VERSION 5.8 ;
BUSBITCHARS "[]" ;
DIVIDERCHAR "/" ;
UNITS
    DATABASE MICRONS 1000 ;
END UNITS

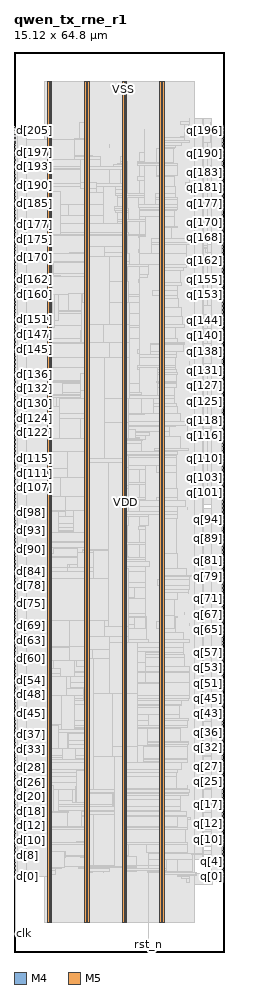
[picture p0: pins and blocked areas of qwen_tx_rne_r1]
MACRO qwen_tx_rne_r1
  FOREIGN qwen_tx_rne_r1 0 0 ;
  CLASS BLOCK ;
  SIZE 15.12 BY 64.8 ;
  PIN clk
    DIRECTION INPUT ;
    USE SIGNAL ;
    PORT
      LAYER M4 ;
        RECT  0.054 1.296 0.138 1.32 ;
    END
    PORT
      LAYER M4 ;
        RECT  0.108 1.296 0.227 1.416 ;
    END
  END clk
  PIN d[0]
    DIRECTION INPUT ;
    USE SIGNAL ;
    PORT
      LAYER M4 ;
        RECT  0.054 5.424 0.138 5.448 ;
    END
  END d[0]
  PIN d[100]
    DIRECTION INPUT ;
    USE SIGNAL ;
    PORT
      LAYER M4 ;
        RECT  0.054 31.584 0.138 31.608 ;
    END
  END d[100]
  PIN d[101]
    DIRECTION INPUT ;
    USE SIGNAL ;
    PORT
      LAYER M4 ;
        RECT  0.054 31.872 0.138 31.896 ;
    END
  END d[101]
  PIN d[102]
    DIRECTION INPUT ;
    USE SIGNAL ;
    PORT
      LAYER M4 ;
        RECT  0.054 32.112 0.138 32.136 ;
    END
  END d[102]
  PIN d[103]
    DIRECTION INPUT ;
    USE SIGNAL ;
    PORT
      LAYER M4 ;
        RECT  0.054 32.4 0.138 32.424 ;
    END
  END d[103]
  PIN d[104]
    DIRECTION INPUT ;
    USE SIGNAL ;
    PORT
      LAYER M4 ;
        RECT  0.054 32.64 0.138 32.664 ;
    END
  END d[104]
  PIN d[105]
    DIRECTION INPUT ;
    USE SIGNAL ;
    PORT
      LAYER M4 ;
        RECT  0.054 32.928 0.138 32.952 ;
    END
  END d[105]
  PIN d[106]
    DIRECTION INPUT ;
    USE SIGNAL ;
    PORT
      LAYER M4 ;
        RECT  0.054 33.168 0.138 33.192 ;
    END
  END d[106]
  PIN d[107]
    DIRECTION INPUT ;
    USE SIGNAL ;
    PORT
      LAYER M4 ;
        RECT  0.054 33.456 0.138 33.48 ;
    END
  END d[107]
  PIN d[108]
    DIRECTION INPUT ;
    USE SIGNAL ;
    PORT
      LAYER M4 ;
        RECT  0.054 33.696 0.138 33.72 ;
    END
  END d[108]
  PIN d[109]
    DIRECTION INPUT ;
    USE SIGNAL ;
    PORT
      LAYER M4 ;
        RECT  0.054 33.984 0.138 34.008 ;
    END
  END d[109]
  PIN d[10]
    DIRECTION INPUT ;
    USE SIGNAL ;
    PORT
      LAYER M4 ;
        RECT  0.054 8.016 0.138 8.04 ;
    END
  END d[10]
  PIN d[110]
    DIRECTION INPUT ;
    USE SIGNAL ;
    PORT
      LAYER M4 ;
        RECT  0.054 34.224 0.138 34.248 ;
    END
  END d[110]
  PIN d[111]
    DIRECTION INPUT ;
    USE SIGNAL ;
    PORT
      LAYER M4 ;
        RECT  0.054 34.464 0.138 34.488 ;
    END
  END d[111]
  PIN d[112]
    DIRECTION INPUT ;
    USE SIGNAL ;
    PORT
      LAYER M4 ;
        RECT  0.054 34.752 0.138 34.776 ;
    END
  END d[112]
  PIN d[113]
    DIRECTION INPUT ;
    USE SIGNAL ;
    PORT
      LAYER M4 ;
        RECT  0.054 34.992 0.138 35.016 ;
    END
  END d[113]
  PIN d[114]
    DIRECTION INPUT ;
    USE SIGNAL ;
    PORT
      LAYER M4 ;
        RECT  0.054 35.28 0.138 35.304 ;
    END
  END d[114]
  PIN d[115]
    DIRECTION INPUT ;
    USE SIGNAL ;
    PORT
      LAYER M4 ;
        RECT  0.054 35.52 0.138 35.544 ;
    END
  END d[115]
  PIN d[116]
    DIRECTION INPUT ;
    USE SIGNAL ;
    PORT
      LAYER M4 ;
        RECT  0.054 35.808 0.138 35.832 ;
    END
  END d[116]
  PIN d[117]
    DIRECTION INPUT ;
    USE SIGNAL ;
    PORT
      LAYER M4 ;
        RECT  0.054 36.048 0.138 36.072 ;
    END
  END d[117]
  PIN d[118]
    DIRECTION INPUT ;
    USE SIGNAL ;
    PORT
      LAYER M4 ;
        RECT  0.054 36.336 0.138 36.36 ;
    END
  END d[118]
  PIN d[119]
    DIRECTION INPUT ;
    USE SIGNAL ;
    PORT
      LAYER M4 ;
        RECT  0.054 36.576 0.138 36.6 ;
    END
  END d[119]
  PIN d[11]
    DIRECTION INPUT ;
    USE SIGNAL ;
    PORT
      LAYER M4 ;
        RECT  0.054 8.256 0.138 8.28 ;
    END
  END d[11]
  PIN d[120]
    DIRECTION INPUT ;
    USE SIGNAL ;
    PORT
      LAYER M4 ;
        RECT  0.054 36.864 0.138 36.888 ;
    END
  END d[120]
  PIN d[121]
    DIRECTION INPUT ;
    USE SIGNAL ;
    PORT
      LAYER M4 ;
        RECT  0.054 37.104 0.138 37.128 ;
    END
  END d[121]
  PIN d[122]
    DIRECTION INPUT ;
    USE SIGNAL ;
    PORT
      LAYER M4 ;
        RECT  0.054 37.392 0.138 37.416 ;
    END
  END d[122]
  PIN d[123]
    DIRECTION INPUT ;
    USE SIGNAL ;
    PORT
      LAYER M4 ;
        RECT  0.054 37.632 0.138 37.656 ;
    END
  END d[123]
  PIN d[124]
    DIRECTION INPUT ;
    USE SIGNAL ;
    PORT
      LAYER M4 ;
        RECT  0.054 37.872 0.138 37.896 ;
    END
  END d[124]
  PIN d[125]
    DIRECTION INPUT ;
    USE SIGNAL ;
    PORT
      LAYER M4 ;
        RECT  0.054 38.16 0.138 38.184 ;
    END
  END d[125]
  PIN d[126]
    DIRECTION INPUT ;
    USE SIGNAL ;
    PORT
      LAYER M4 ;
        RECT  0.054 38.4 0.138 38.424 ;
    END
  END d[126]
  PIN d[127]
    DIRECTION INPUT ;
    USE SIGNAL ;
    PORT
      LAYER M4 ;
        RECT  0.054 38.688 0.138 38.712 ;
    END
  END d[127]
  PIN d[128]
    DIRECTION INPUT ;
    USE SIGNAL ;
    PORT
      LAYER M4 ;
        RECT  0.054 38.928 0.138 38.952 ;
    END
  END d[128]
  PIN d[129]
    DIRECTION INPUT ;
    USE SIGNAL ;
    PORT
      LAYER M4 ;
        RECT  0.054 39.216 0.138 39.24 ;
    END
  END d[129]
  PIN d[12]
    DIRECTION INPUT ;
    USE SIGNAL ;
    PORT
      LAYER M4 ;
        RECT  0.054 8.544 0.138 8.568 ;
    END
  END d[12]
  PIN d[130]
    DIRECTION INPUT ;
    USE SIGNAL ;
    PORT
      LAYER M4 ;
        RECT  0.054 39.456 0.138 39.48 ;
    END
  END d[130]
  PIN d[131]
    DIRECTION INPUT ;
    USE SIGNAL ;
    PORT
      LAYER M4 ;
        RECT  0.054 39.744 0.138 39.768 ;
    END
  END d[131]
  PIN d[132]
    DIRECTION INPUT ;
    USE SIGNAL ;
    PORT
      LAYER M4 ;
        RECT  0.054 39.984 0.138 40.008 ;
    END
  END d[132]
  PIN d[133]
    DIRECTION INPUT ;
    USE SIGNAL ;
    PORT
      LAYER M4 ;
        RECT  0.054 40.272 0.138 40.296 ;
    END
  END d[133]
  PIN d[134]
    DIRECTION INPUT ;
    USE SIGNAL ;
    PORT
      LAYER M4 ;
        RECT  0.054 40.512 0.138 40.536 ;
    END
  END d[134]
  PIN d[135]
    DIRECTION INPUT ;
    USE SIGNAL ;
    PORT
      LAYER M4 ;
        RECT  0.054 40.8 0.138 40.824 ;
    END
  END d[135]
  PIN d[136]
    DIRECTION INPUT ;
    USE SIGNAL ;
    PORT
      LAYER M4 ;
        RECT  0.054 41.04 0.138 41.064 ;
    END
  END d[136]
  PIN d[137]
    DIRECTION INPUT ;
    USE SIGNAL ;
    PORT
      LAYER M4 ;
        RECT  0.054 41.28 0.138 41.304 ;
    END
  END d[137]
  PIN d[138]
    DIRECTION INPUT ;
    USE SIGNAL ;
    PORT
      LAYER M4 ;
        RECT  0.054 41.568 0.138 41.592 ;
    END
  END d[138]
  PIN d[139]
    DIRECTION INPUT ;
    USE SIGNAL ;
    PORT
      LAYER M4 ;
        RECT  0.054 41.808 0.138 41.832 ;
    END
  END d[139]
  PIN d[13]
    DIRECTION INPUT ;
    USE SIGNAL ;
    PORT
      LAYER M4 ;
        RECT  0.054 8.784 0.138 8.808 ;
    END
  END d[13]
  PIN d[140]
    DIRECTION INPUT ;
    USE SIGNAL ;
    PORT
      LAYER M4 ;
        RECT  0.054 42.096 0.138 42.12 ;
    END
  END d[140]
  PIN d[141]
    DIRECTION INPUT ;
    USE SIGNAL ;
    PORT
      LAYER M4 ;
        RECT  0.054 42.336 0.138 42.36 ;
    END
  END d[141]
  PIN d[142]
    DIRECTION INPUT ;
    USE SIGNAL ;
    PORT
      LAYER M4 ;
        RECT  0.054 42.624 0.138 42.648 ;
    END
  END d[142]
  PIN d[143]
    DIRECTION INPUT ;
    USE SIGNAL ;
    PORT
      LAYER M4 ;
        RECT  0.054 42.864 0.138 42.888 ;
    END
  END d[143]
  PIN d[144]
    DIRECTION INPUT ;
    USE SIGNAL ;
    PORT
      LAYER M4 ;
        RECT  0.054 43.152 0.138 43.176 ;
    END
  END d[144]
  PIN d[145]
    DIRECTION INPUT ;
    USE SIGNAL ;
    PORT
      LAYER M4 ;
        RECT  0.054 43.392 0.138 43.416 ;
    END
  END d[145]
  PIN d[146]
    DIRECTION INPUT ;
    USE SIGNAL ;
    PORT
      LAYER M4 ;
        RECT  0.054 43.68 0.138 43.704 ;
    END
  END d[146]
  PIN d[147]
    DIRECTION INPUT ;
    USE SIGNAL ;
    PORT
      LAYER M4 ;
        RECT  0.054 43.92 0.138 43.944 ;
    END
  END d[147]
  PIN d[148]
    DIRECTION INPUT ;
    USE SIGNAL ;
    PORT
      LAYER M4 ;
        RECT  0.054 44.208 0.138 44.232 ;
    END
  END d[148]
  PIN d[149]
    DIRECTION INPUT ;
    USE SIGNAL ;
    PORT
      LAYER M4 ;
        RECT  0.054 44.448 0.138 44.472 ;
    END
  END d[149]
  PIN d[14]
    DIRECTION INPUT ;
    USE SIGNAL ;
    PORT
      LAYER M4 ;
        RECT  0.054 9.072 0.138 9.096 ;
    END
  END d[14]
  PIN d[150]
    DIRECTION INPUT ;
    USE SIGNAL ;
    PORT
      LAYER M4 ;
        RECT  0.054 44.688 0.138 44.712 ;
    END
  END d[150]
  PIN d[151]
    DIRECTION INPUT ;
    USE SIGNAL ;
    PORT
      LAYER M4 ;
        RECT  0.054 44.976 0.138 45 ;
    END
  END d[151]
  PIN d[152]
    DIRECTION INPUT ;
    USE SIGNAL ;
    PORT
      LAYER M4 ;
        RECT  0.054 45.216 0.138 45.24 ;
    END
  END d[152]
  PIN d[153]
    DIRECTION INPUT ;
    USE SIGNAL ;
    PORT
      LAYER M4 ;
        RECT  0.054 45.504 0.138 45.528 ;
    END
  END d[153]
  PIN d[154]
    DIRECTION INPUT ;
    USE SIGNAL ;
    PORT
      LAYER M4 ;
        RECT  0.054 45.744 0.138 45.768 ;
    END
  END d[154]
  PIN d[155]
    DIRECTION INPUT ;
    USE SIGNAL ;
    PORT
      LAYER M4 ;
        RECT  0.054 46.032 0.138 46.056 ;
    END
  END d[155]
  PIN d[156]
    DIRECTION INPUT ;
    USE SIGNAL ;
    PORT
      LAYER M4 ;
        RECT  0.054 46.272 0.138 46.296 ;
    END
  END d[156]
  PIN d[157]
    DIRECTION INPUT ;
    USE SIGNAL ;
    PORT
      LAYER M4 ;
        RECT  0.054 46.56 0.138 46.584 ;
    END
  END d[157]
  PIN d[158]
    DIRECTION INPUT ;
    USE SIGNAL ;
    PORT
      LAYER M4 ;
        RECT  0.054 46.8 0.138 46.824 ;
    END
  END d[158]
  PIN d[159]
    DIRECTION INPUT ;
    USE SIGNAL ;
    PORT
      LAYER M4 ;
        RECT  0.054 47.088 0.138 47.112 ;
    END
  END d[159]
  PIN d[15]
    DIRECTION INPUT ;
    USE SIGNAL ;
    PORT
      LAYER M4 ;
        RECT  0.054 9.312 0.138 9.336 ;
    END
  END d[15]
  PIN d[160]
    DIRECTION INPUT ;
    USE SIGNAL ;
    PORT
      LAYER M4 ;
        RECT  0.054 47.328 0.138 47.352 ;
    END
  END d[160]
  PIN d[161]
    DIRECTION INPUT ;
    USE SIGNAL ;
    PORT
      LAYER M4 ;
        RECT  0.054 47.568 0.138 47.592 ;
    END
  END d[161]
  PIN d[162]
    DIRECTION INPUT ;
    USE SIGNAL ;
    PORT
      LAYER M4 ;
        RECT  0.054 47.856 0.138 47.88 ;
    END
  END d[162]
  PIN d[163]
    DIRECTION INPUT ;
    USE SIGNAL ;
    PORT
      LAYER M4 ;
        RECT  0.054 48.096 0.138 48.12 ;
    END
  END d[163]
  PIN d[164]
    DIRECTION INPUT ;
    USE SIGNAL ;
    PORT
      LAYER M4 ;
        RECT  0.054 48.384 0.138 48.408 ;
    END
  END d[164]
  PIN d[165]
    DIRECTION INPUT ;
    USE SIGNAL ;
    PORT
      LAYER M4 ;
        RECT  0.054 48.624 0.138 48.648 ;
    END
  END d[165]
  PIN d[166]
    DIRECTION INPUT ;
    USE SIGNAL ;
    PORT
      LAYER M4 ;
        RECT  0.054 48.912 0.138 48.936 ;
    END
  END d[166]
  PIN d[167]
    DIRECTION INPUT ;
    USE SIGNAL ;
    PORT
      LAYER M4 ;
        RECT  0.054 49.152 0.138 49.176 ;
    END
  END d[167]
  PIN d[168]
    DIRECTION INPUT ;
    USE SIGNAL ;
    PORT
      LAYER M4 ;
        RECT  0.054 49.44 0.138 49.464 ;
    END
  END d[168]
  PIN d[169]
    DIRECTION INPUT ;
    USE SIGNAL ;
    PORT
      LAYER M4 ;
        RECT  0.054 49.68 0.138 49.704 ;
    END
  END d[169]
  PIN d[16]
    DIRECTION INPUT ;
    USE SIGNAL ;
    PORT
      LAYER M4 ;
        RECT  0.054 9.6 0.138 9.624 ;
    END
  END d[16]
  PIN d[170]
    DIRECTION INPUT ;
    USE SIGNAL ;
    PORT
      LAYER M4 ;
        RECT  0.054 49.968 0.138 49.992 ;
    END
  END d[170]
  PIN d[171]
    DIRECTION INPUT ;
    USE SIGNAL ;
    PORT
      LAYER M4 ;
        RECT  0.054 50.208 0.138 50.232 ;
    END
  END d[171]
  PIN d[172]
    DIRECTION INPUT ;
    USE SIGNAL ;
    PORT
      LAYER M4 ;
        RECT  0.054 50.496 0.138 50.52 ;
    END
  END d[172]
  PIN d[173]
    DIRECTION INPUT ;
    USE SIGNAL ;
    PORT
      LAYER M4 ;
        RECT  0.054 50.736 0.138 50.76 ;
    END
  END d[173]
  PIN d[174]
    DIRECTION INPUT ;
    USE SIGNAL ;
    PORT
      LAYER M4 ;
        RECT  0.054 50.976 0.138 51 ;
    END
  END d[174]
  PIN d[175]
    DIRECTION INPUT ;
    USE SIGNAL ;
    PORT
      LAYER M4 ;
        RECT  0.054 51.264 0.138 51.288 ;
    END
  END d[175]
  PIN d[176]
    DIRECTION INPUT ;
    USE SIGNAL ;
    PORT
      LAYER M4 ;
        RECT  0.054 51.504 0.138 51.528 ;
    END
  END d[176]
  PIN d[177]
    DIRECTION INPUT ;
    USE SIGNAL ;
    PORT
      LAYER M4 ;
        RECT  0.054 51.792 0.138 51.816 ;
    END
  END d[177]
  PIN d[178]
    DIRECTION INPUT ;
    USE SIGNAL ;
    PORT
      LAYER M4 ;
        RECT  0.054 52.032 0.138 52.056 ;
    END
  END d[178]
  PIN d[179]
    DIRECTION INPUT ;
    USE SIGNAL ;
    PORT
      LAYER M4 ;
        RECT  0.054 52.32 0.138 52.344 ;
    END
  END d[179]
  PIN d[17]
    DIRECTION INPUT ;
    USE SIGNAL ;
    PORT
      LAYER M4 ;
        RECT  0.054 9.84 0.138 9.864 ;
    END
  END d[17]
  PIN d[180]
    DIRECTION INPUT ;
    USE SIGNAL ;
    PORT
      LAYER M4 ;
        RECT  0.054 52.56 0.138 52.584 ;
    END
  END d[180]
  PIN d[181]
    DIRECTION INPUT ;
    USE SIGNAL ;
    PORT
      LAYER M4 ;
        RECT  0.054 52.848 0.138 52.872 ;
    END
  END d[181]
  PIN d[182]
    DIRECTION INPUT ;
    USE SIGNAL ;
    PORT
      LAYER M4 ;
        RECT  0.054 53.088 0.138 53.112 ;
    END
  END d[182]
  PIN d[183]
    DIRECTION INPUT ;
    USE SIGNAL ;
    PORT
      LAYER M4 ;
        RECT  0.054 53.376 0.138 53.4 ;
    END
  END d[183]
  PIN d[184]
    DIRECTION INPUT ;
    USE SIGNAL ;
    PORT
      LAYER M4 ;
        RECT  0.054 53.616 0.138 53.64 ;
    END
  END d[184]
  PIN d[185]
    DIRECTION INPUT ;
    USE SIGNAL ;
    PORT
      LAYER M4 ;
        RECT  0.054 53.904 0.138 53.928 ;
    END
  END d[185]
  PIN d[186]
    DIRECTION INPUT ;
    USE SIGNAL ;
    PORT
      LAYER M4 ;
        RECT  0.054 54.144 0.138 54.168 ;
    END
  END d[186]
  PIN d[187]
    DIRECTION INPUT ;
    USE SIGNAL ;
    PORT
      LAYER M4 ;
        RECT  0.054 54.384 0.138 54.408 ;
    END
  END d[187]
  PIN d[188]
    DIRECTION INPUT ;
    USE SIGNAL ;
    PORT
      LAYER M4 ;
        RECT  0.054 54.672 0.138 54.696 ;
    END
  END d[188]
  PIN d[189]
    DIRECTION INPUT ;
    USE SIGNAL ;
    PORT
      LAYER M4 ;
        RECT  0.054 54.912 0.138 54.936 ;
    END
  END d[189]
  PIN d[18]
    DIRECTION INPUT ;
    USE SIGNAL ;
    PORT
      LAYER M4 ;
        RECT  0.054 10.128 0.138 10.152 ;
    END
  END d[18]
  PIN d[190]
    DIRECTION INPUT ;
    USE SIGNAL ;
    PORT
      LAYER M4 ;
        RECT  0.054 55.2 0.138 55.224 ;
    END
  END d[190]
  PIN d[191]
    DIRECTION INPUT ;
    USE SIGNAL ;
    PORT
      LAYER M4 ;
        RECT  0.054 55.44 0.138 55.464 ;
    END
  END d[191]
  PIN d[192]
    DIRECTION INPUT ;
    USE SIGNAL ;
    PORT
      LAYER M4 ;
        RECT  0.054 55.728 0.138 55.752 ;
    END
  END d[192]
  PIN d[193]
    DIRECTION INPUT ;
    USE SIGNAL ;
    PORT
      LAYER M4 ;
        RECT  0.054 55.968 0.138 55.992 ;
    END
  END d[193]
  PIN d[194]
    DIRECTION INPUT ;
    USE SIGNAL ;
    PORT
      LAYER M4 ;
        RECT  0.054 56.256 0.138 56.28 ;
    END
  END d[194]
  PIN d[195]
    DIRECTION INPUT ;
    USE SIGNAL ;
    PORT
      LAYER M4 ;
        RECT  0.054 56.496 0.138 56.52 ;
    END
  END d[195]
  PIN d[196]
    DIRECTION INPUT ;
    USE SIGNAL ;
    PORT
      LAYER M4 ;
        RECT  0.054 56.784 0.138 56.808 ;
    END
  END d[196]
  PIN d[197]
    DIRECTION INPUT ;
    USE SIGNAL ;
    PORT
      LAYER M4 ;
        RECT  0.054 57.024 0.138 57.048 ;
    END
  END d[197]
  PIN d[198]
    DIRECTION INPUT ;
    USE SIGNAL ;
    PORT
      LAYER M4 ;
        RECT  0.054 57.312 0.138 57.336 ;
    END
  END d[198]
  PIN d[199]
    DIRECTION INPUT ;
    USE SIGNAL ;
    PORT
      LAYER M4 ;
        RECT  0.054 57.552 0.138 57.576 ;
    END
  END d[199]
  PIN d[19]
    DIRECTION INPUT ;
    USE SIGNAL ;
    PORT
      LAYER M4 ;
        RECT  0.054 10.368 0.138 10.392 ;
    END
  END d[19]
  PIN d[1]
    DIRECTION INPUT ;
    USE SIGNAL ;
    PORT
      LAYER M4 ;
        RECT  0.054 5.664 0.138 5.688 ;
    END
  END d[1]
  PIN d[200]
    DIRECTION INPUT ;
    USE SIGNAL ;
    PORT
      LAYER M4 ;
        RECT  0.054 57.792 0.138 57.816 ;
    END
  END d[200]
  PIN d[201]
    DIRECTION INPUT ;
    USE SIGNAL ;
    PORT
      LAYER M4 ;
        RECT  0.054 58.08 0.138 58.104 ;
    END
  END d[201]
  PIN d[202]
    DIRECTION INPUT ;
    USE SIGNAL ;
    PORT
      LAYER M4 ;
        RECT  0.054 58.32 0.138 58.344 ;
    END
    PORT
      LAYER M4 ;
        RECT  0.025 58.224 0.108 58.344 ;
    END
  END d[202]
  PIN d[203]
    DIRECTION INPUT ;
    USE SIGNAL ;
    PORT
      LAYER M4 ;
        RECT  0.054 58.608 0.138 58.632 ;
    END
  END d[203]
  PIN d[204]
    DIRECTION INPUT ;
    USE SIGNAL ;
    PORT
      LAYER M4 ;
        RECT  0.054 58.848 0.138 58.872 ;
    END
  END d[204]
  PIN d[205]
    DIRECTION INPUT ;
    USE SIGNAL ;
    PORT
      LAYER M4 ;
        RECT  0.054 59.136 0.138 59.16 ;
    END
  END d[205]
  PIN d[206]
    DIRECTION INPUT ;
    USE SIGNAL ;
    PORT
      LAYER M4 ;
        RECT  0.054 59.376 0.138 59.4 ;
    END
    PORT
      LAYER M4 ;
        RECT  0.025 59.376 0.108 59.4 ;
    END
  END d[206]
  PIN d[20]
    DIRECTION INPUT ;
    USE SIGNAL ;
    PORT
      LAYER M4 ;
        RECT  0.054 10.608 0.138 10.632 ;
    END
  END d[20]
  PIN d[21]
    DIRECTION INPUT ;
    USE SIGNAL ;
    PORT
      LAYER M4 ;
        RECT  0.054 10.896 0.138 10.92 ;
    END
  END d[21]
  PIN d[22]
    DIRECTION INPUT ;
    USE SIGNAL ;
    PORT
      LAYER M4 ;
        RECT  0.054 11.136 0.138 11.16 ;
    END
  END d[22]
  PIN d[23]
    DIRECTION INPUT ;
    USE SIGNAL ;
    PORT
      LAYER M4 ;
        RECT  0.054 11.424 0.138 11.448 ;
    END
  END d[23]
  PIN d[24]
    DIRECTION INPUT ;
    USE SIGNAL ;
    PORT
      LAYER M4 ;
        RECT  0.054 11.664 0.138 11.688 ;
    END
  END d[24]
  PIN d[25]
    DIRECTION INPUT ;
    USE SIGNAL ;
    PORT
      LAYER M4 ;
        RECT  0.054 11.952 0.138 11.976 ;
    END
  END d[25]
  PIN d[26]
    DIRECTION INPUT ;
    USE SIGNAL ;
    PORT
      LAYER M4 ;
        RECT  0.054 12.192 0.138 12.216 ;
    END
  END d[26]
  PIN d[27]
    DIRECTION INPUT ;
    USE SIGNAL ;
    PORT
      LAYER M4 ;
        RECT  0.054 12.48 0.138 12.504 ;
    END
  END d[27]
  PIN d[28]
    DIRECTION INPUT ;
    USE SIGNAL ;
    PORT
      LAYER M4 ;
        RECT  0.054 12.72 0.138 12.744 ;
    END
  END d[28]
  PIN d[29]
    DIRECTION INPUT ;
    USE SIGNAL ;
    PORT
      LAYER M4 ;
        RECT  0.054 13.008 0.138 13.032 ;
    END
  END d[29]
  PIN d[2]
    DIRECTION INPUT ;
    USE SIGNAL ;
    PORT
      LAYER M4 ;
        RECT  0.054 5.904 0.138 5.928 ;
    END
  END d[2]
  PIN d[30]
    DIRECTION INPUT ;
    USE SIGNAL ;
    PORT
      LAYER M4 ;
        RECT  0.054 13.248 0.138 13.272 ;
    END
  END d[30]
  PIN d[31]
    DIRECTION INPUT ;
    USE SIGNAL ;
    PORT
      LAYER M4 ;
        RECT  0.054 13.536 0.138 13.56 ;
    END
  END d[31]
  PIN d[32]
    DIRECTION INPUT ;
    USE SIGNAL ;
    PORT
      LAYER M4 ;
        RECT  0.054 13.776 0.138 13.8 ;
    END
  END d[32]
  PIN d[33]
    DIRECTION INPUT ;
    USE SIGNAL ;
    PORT
      LAYER M4 ;
        RECT  0.054 14.016 0.138 14.04 ;
    END
  END d[33]
  PIN d[34]
    DIRECTION INPUT ;
    USE SIGNAL ;
    PORT
      LAYER M4 ;
        RECT  0.054 14.304 0.138 14.328 ;
    END
  END d[34]
  PIN d[35]
    DIRECTION INPUT ;
    USE SIGNAL ;
    PORT
      LAYER M4 ;
        RECT  0.054 14.544 0.138 14.568 ;
    END
  END d[35]
  PIN d[36]
    DIRECTION INPUT ;
    USE SIGNAL ;
    PORT
      LAYER M4 ;
        RECT  0.054 14.832 0.138 14.856 ;
    END
  END d[36]
  PIN d[37]
    DIRECTION INPUT ;
    USE SIGNAL ;
    PORT
      LAYER M4 ;
        RECT  0.054 15.072 0.138 15.096 ;
    END
  END d[37]
  PIN d[38]
    DIRECTION INPUT ;
    USE SIGNAL ;
    PORT
      LAYER M4 ;
        RECT  0.054 15.36 0.138 15.384 ;
    END
  END d[38]
  PIN d[39]
    DIRECTION INPUT ;
    USE SIGNAL ;
    PORT
      LAYER M4 ;
        RECT  0.054 15.6 0.138 15.624 ;
    END
  END d[39]
  PIN d[3]
    DIRECTION INPUT ;
    USE SIGNAL ;
    PORT
      LAYER M4 ;
        RECT  0.054 6.192 0.138 6.216 ;
    END
  END d[3]
  PIN d[40]
    DIRECTION INPUT ;
    USE SIGNAL ;
    PORT
      LAYER M4 ;
        RECT  0.054 15.888 0.138 15.912 ;
    END
  END d[40]
  PIN d[41]
    DIRECTION INPUT ;
    USE SIGNAL ;
    PORT
      LAYER M4 ;
        RECT  0.054 16.128 0.138 16.152 ;
    END
  END d[41]
  PIN d[42]
    DIRECTION INPUT ;
    USE SIGNAL ;
    PORT
      LAYER M4 ;
        RECT  0.054 16.416 0.138 16.44 ;
    END
  END d[42]
  PIN d[43]
    DIRECTION INPUT ;
    USE SIGNAL ;
    PORT
      LAYER M4 ;
        RECT  0.054 16.656 0.138 16.68 ;
    END
  END d[43]
  PIN d[44]
    DIRECTION INPUT ;
    USE SIGNAL ;
    PORT
      LAYER M4 ;
        RECT  0.054 16.944 0.138 16.968 ;
    END
  END d[44]
  PIN d[45]
    DIRECTION INPUT ;
    USE SIGNAL ;
    PORT
      LAYER M4 ;
        RECT  0.054 17.184 0.138 17.208 ;
    END
  END d[45]
  PIN d[46]
    DIRECTION INPUT ;
    USE SIGNAL ;
    PORT
      LAYER M4 ;
        RECT  0.054 17.424 0.138 17.448 ;
    END
  END d[46]
  PIN d[47]
    DIRECTION INPUT ;
    USE SIGNAL ;
    PORT
      LAYER M4 ;
        RECT  0.054 17.712 0.138 17.736 ;
    END
  END d[47]
  PIN d[48]
    DIRECTION INPUT ;
    USE SIGNAL ;
    PORT
      LAYER M4 ;
        RECT  0.054 17.952 0.138 17.976 ;
    END
  END d[48]
  PIN d[49]
    DIRECTION INPUT ;
    USE SIGNAL ;
    PORT
      LAYER M4 ;
        RECT  0.054 18.24 0.138 18.264 ;
    END
  END d[49]
  PIN d[4]
    DIRECTION INPUT ;
    USE SIGNAL ;
    PORT
      LAYER M4 ;
        RECT  0.054 6.432 0.138 6.456 ;
    END
  END d[4]
  PIN d[50]
    DIRECTION INPUT ;
    USE SIGNAL ;
    PORT
      LAYER M4 ;
        RECT  0.054 18.48 0.138 18.504 ;
    END
  END d[50]
  PIN d[51]
    DIRECTION INPUT ;
    USE SIGNAL ;
    PORT
      LAYER M4 ;
        RECT  0.054 18.768 0.138 18.792 ;
    END
  END d[51]
  PIN d[52]
    DIRECTION INPUT ;
    USE SIGNAL ;
    PORT
      LAYER M4 ;
        RECT  0.054 19.008 0.138 19.032 ;
    END
  END d[52]
  PIN d[53]
    DIRECTION INPUT ;
    USE SIGNAL ;
    PORT
      LAYER M4 ;
        RECT  0.054 19.296 0.138 19.32 ;
    END
  END d[53]
  PIN d[54]
    DIRECTION INPUT ;
    USE SIGNAL ;
    PORT
      LAYER M4 ;
        RECT  0.054 19.536 0.138 19.56 ;
    END
  END d[54]
  PIN d[55]
    DIRECTION INPUT ;
    USE SIGNAL ;
    PORT
      LAYER M4 ;
        RECT  0.054 19.824 0.138 19.848 ;
    END
  END d[55]
  PIN d[56]
    DIRECTION INPUT ;
    USE SIGNAL ;
    PORT
      LAYER M4 ;
        RECT  0.054 20.064 0.138 20.088 ;
    END
  END d[56]
  PIN d[57]
    DIRECTION INPUT ;
    USE SIGNAL ;
    PORT
      LAYER M4 ;
        RECT  0.054 20.352 0.138 20.376 ;
    END
  END d[57]
  PIN d[58]
    DIRECTION INPUT ;
    USE SIGNAL ;
    PORT
      LAYER M4 ;
        RECT  0.054 20.592 0.138 20.616 ;
    END
  END d[58]
  PIN d[59]
    DIRECTION INPUT ;
    USE SIGNAL ;
    PORT
      LAYER M4 ;
        RECT  0.054 20.832 0.138 20.856 ;
    END
  END d[59]
  PIN d[5]
    DIRECTION INPUT ;
    USE SIGNAL ;
    PORT
      LAYER M4 ;
        RECT  0.054 6.72 0.138 6.744 ;
    END
  END d[5]
  PIN d[60]
    DIRECTION INPUT ;
    USE SIGNAL ;
    PORT
      LAYER M4 ;
        RECT  0.054 21.12 0.138 21.144 ;
    END
  END d[60]
  PIN d[61]
    DIRECTION INPUT ;
    USE SIGNAL ;
    PORT
      LAYER M4 ;
        RECT  0.054 21.36 0.138 21.384 ;
    END
  END d[61]
  PIN d[62]
    DIRECTION INPUT ;
    USE SIGNAL ;
    PORT
      LAYER M4 ;
        RECT  0.054 21.648 0.138 21.672 ;
    END
  END d[62]
  PIN d[63]
    DIRECTION INPUT ;
    USE SIGNAL ;
    PORT
      LAYER M4 ;
        RECT  0.054 21.888 0.138 21.912 ;
    END
  END d[63]
  PIN d[64]
    DIRECTION INPUT ;
    USE SIGNAL ;
    PORT
      LAYER M4 ;
        RECT  0.054 22.176 0.138 22.2 ;
    END
  END d[64]
  PIN d[65]
    DIRECTION INPUT ;
    USE SIGNAL ;
    PORT
      LAYER M4 ;
        RECT  0.054 22.416 0.138 22.44 ;
    END
  END d[65]
  PIN d[66]
    DIRECTION INPUT ;
    USE SIGNAL ;
    PORT
      LAYER M4 ;
        RECT  0.054 22.704 0.138 22.728 ;
    END
  END d[66]
  PIN d[67]
    DIRECTION INPUT ;
    USE SIGNAL ;
    PORT
      LAYER M4 ;
        RECT  0.054 22.944 0.138 22.968 ;
    END
  END d[67]
  PIN d[68]
    DIRECTION INPUT ;
    USE SIGNAL ;
    PORT
      LAYER M4 ;
        RECT  0.054 23.232 0.138 23.256 ;
    END
  END d[68]
  PIN d[69]
    DIRECTION INPUT ;
    USE SIGNAL ;
    PORT
      LAYER M4 ;
        RECT  0.054 23.472 0.138 23.496 ;
    END
  END d[69]
  PIN d[6]
    DIRECTION INPUT ;
    USE SIGNAL ;
    PORT
      LAYER M4 ;
        RECT  0.054 6.96 0.138 6.984 ;
    END
  END d[6]
  PIN d[70]
    DIRECTION INPUT ;
    USE SIGNAL ;
    PORT
      LAYER M4 ;
        RECT  0.054 23.76 0.138 23.784 ;
    END
  END d[70]
  PIN d[71]
    DIRECTION INPUT ;
    USE SIGNAL ;
    PORT
      LAYER M4 ;
        RECT  0.054 24 0.138 24.024 ;
    END
  END d[71]
  PIN d[72]
    DIRECTION INPUT ;
    USE SIGNAL ;
    PORT
      LAYER M4 ;
        RECT  0.054 24.24 0.138 24.264 ;
    END
  END d[72]
  PIN d[73]
    DIRECTION INPUT ;
    USE SIGNAL ;
    PORT
      LAYER M4 ;
        RECT  0.054 24.528 0.138 24.552 ;
    END
  END d[73]
  PIN d[74]
    DIRECTION INPUT ;
    USE SIGNAL ;
    PORT
      LAYER M4 ;
        RECT  0.054 24.768 0.138 24.792 ;
    END
  END d[74]
  PIN d[75]
    DIRECTION INPUT ;
    USE SIGNAL ;
    PORT
      LAYER M4 ;
        RECT  0.054 25.056 0.138 25.08 ;
    END
  END d[75]
  PIN d[76]
    DIRECTION INPUT ;
    USE SIGNAL ;
    PORT
      LAYER M4 ;
        RECT  0.054 25.296 0.138 25.32 ;
    END
  END d[76]
  PIN d[77]
    DIRECTION INPUT ;
    USE SIGNAL ;
    PORT
      LAYER M4 ;
        RECT  0.054 25.584 0.138 25.608 ;
    END
  END d[77]
  PIN d[78]
    DIRECTION INPUT ;
    USE SIGNAL ;
    PORT
      LAYER M4 ;
        RECT  0.054 25.824 0.138 25.848 ;
    END
  END d[78]
  PIN d[79]
    DIRECTION INPUT ;
    USE SIGNAL ;
    PORT
      LAYER M4 ;
        RECT  0.054 26.112 0.138 26.136 ;
    END
  END d[79]
  PIN d[7]
    DIRECTION INPUT ;
    USE SIGNAL ;
    PORT
      LAYER M4 ;
        RECT  0.054 7.2 0.138 7.224 ;
    END
  END d[7]
  PIN d[80]
    DIRECTION INPUT ;
    USE SIGNAL ;
    PORT
      LAYER M4 ;
        RECT  0.054 26.352 0.138 26.376 ;
    END
  END d[80]
  PIN d[81]
    DIRECTION INPUT ;
    USE SIGNAL ;
    PORT
      LAYER M4 ;
        RECT  0.054 26.64 0.138 26.664 ;
    END
  END d[81]
  PIN d[82]
    DIRECTION INPUT ;
    USE SIGNAL ;
    PORT
      LAYER M4 ;
        RECT  0.054 26.88 0.138 26.904 ;
    END
  END d[82]
  PIN d[83]
    DIRECTION INPUT ;
    USE SIGNAL ;
    PORT
      LAYER M4 ;
        RECT  0.054 27.168 0.138 27.192 ;
    END
  END d[83]
  PIN d[84]
    DIRECTION INPUT ;
    USE SIGNAL ;
    PORT
      LAYER M4 ;
        RECT  0.054 27.408 0.138 27.432 ;
    END
  END d[84]
  PIN d[85]
    DIRECTION INPUT ;
    USE SIGNAL ;
    PORT
      LAYER M4 ;
        RECT  0.054 27.648 0.138 27.672 ;
    END
  END d[85]
  PIN d[86]
    DIRECTION INPUT ;
    USE SIGNAL ;
    PORT
      LAYER M4 ;
        RECT  0.054 27.936 0.138 27.96 ;
    END
  END d[86]
  PIN d[87]
    DIRECTION INPUT ;
    USE SIGNAL ;
    PORT
      LAYER M4 ;
        RECT  0.054 28.176 0.138 28.2 ;
    END
  END d[87]
  PIN d[88]
    DIRECTION INPUT ;
    USE SIGNAL ;
    PORT
      LAYER M4 ;
        RECT  0.054 28.464 0.138 28.488 ;
    END
  END d[88]
  PIN d[89]
    DIRECTION INPUT ;
    USE SIGNAL ;
    PORT
      LAYER M4 ;
        RECT  0.054 28.704 0.138 28.728 ;
    END
  END d[89]
  PIN d[8]
    DIRECTION INPUT ;
    USE SIGNAL ;
    PORT
      LAYER M4 ;
        RECT  0.054 7.488 0.138 7.512 ;
    END
  END d[8]
  PIN d[90]
    DIRECTION INPUT ;
    USE SIGNAL ;
    PORT
      LAYER M4 ;
        RECT  0.054 28.992 0.138 29.016 ;
    END
  END d[90]
  PIN d[91]
    DIRECTION INPUT ;
    USE SIGNAL ;
    PORT
      LAYER M4 ;
        RECT  0.054 29.232 0.138 29.256 ;
    END
  END d[91]
  PIN d[92]
    DIRECTION INPUT ;
    USE SIGNAL ;
    PORT
      LAYER M4 ;
        RECT  0.054 29.52 0.138 29.544 ;
    END
  END d[92]
  PIN d[93]
    DIRECTION INPUT ;
    USE SIGNAL ;
    PORT
      LAYER M4 ;
        RECT  0.054 29.76 0.138 29.784 ;
    END
  END d[93]
  PIN d[94]
    DIRECTION INPUT ;
    USE SIGNAL ;
    PORT
      LAYER M4 ;
        RECT  0.054 30.048 0.138 30.072 ;
    END
  END d[94]
  PIN d[95]
    DIRECTION INPUT ;
    USE SIGNAL ;
    PORT
      LAYER M4 ;
        RECT  0.054 30.288 0.138 30.312 ;
    END
  END d[95]
  PIN d[96]
    DIRECTION INPUT ;
    USE SIGNAL ;
    PORT
      LAYER M4 ;
        RECT  0.054 30.576 0.138 30.6 ;
    END
  END d[96]
  PIN d[97]
    DIRECTION INPUT ;
    USE SIGNAL ;
    PORT
      LAYER M4 ;
        RECT  0.054 30.816 0.138 30.84 ;
    END
  END d[97]
  PIN d[98]
    DIRECTION INPUT ;
    USE SIGNAL ;
    PORT
      LAYER M4 ;
        RECT  0.054 31.056 0.138 31.08 ;
    END
  END d[98]
  PIN d[99]
    DIRECTION INPUT ;
    USE SIGNAL ;
    PORT
      LAYER M4 ;
        RECT  0.054 31.344 0.138 31.368 ;
    END
  END d[99]
  PIN d[9]
    DIRECTION INPUT ;
    USE SIGNAL ;
    PORT
      LAYER M4 ;
        RECT  0.054 7.728 0.138 7.752 ;
    END
  END d[9]
  PIN q[0]
    DIRECTION OUTPUT ;
    USE SIGNAL ;
    PORT
      LAYER M4 ;
        RECT  14.982 5.424 15.066 5.448 ;
    END
  END q[0]
  PIN q[100]
    DIRECTION OUTPUT ;
    USE SIGNAL ;
    PORT
      LAYER M4 ;
        RECT  14.982 32.784 15.066 32.808 ;
    END
  END q[100]
  PIN q[101]
    DIRECTION OUTPUT ;
    USE SIGNAL ;
    PORT
      LAYER M4 ;
        RECT  14.982 33.072 15.066 33.096 ;
    END
  END q[101]
  PIN q[102]
    DIRECTION OUTPUT ;
    USE SIGNAL ;
    PORT
      LAYER M4 ;
        RECT  14.982 33.36 15.066 33.384 ;
    END
  END q[102]
  PIN q[103]
    DIRECTION OUTPUT ;
    USE SIGNAL ;
    PORT
      LAYER M4 ;
        RECT  14.982 33.6 15.066 33.624 ;
    END
  END q[103]
  PIN q[104]
    DIRECTION OUTPUT ;
    USE SIGNAL ;
    PORT
      LAYER M4 ;
        RECT  14.982 33.888 15.066 33.912 ;
    END
  END q[104]
  PIN q[105]
    DIRECTION OUTPUT ;
    USE SIGNAL ;
    PORT
      LAYER M4 ;
        RECT  14.982 34.176 15.066 34.2 ;
    END
  END q[105]
  PIN q[106]
    DIRECTION OUTPUT ;
    USE SIGNAL ;
    PORT
      LAYER M4 ;
        RECT  14.982 34.464 15.066 34.488 ;
    END
  END q[106]
  PIN q[107]
    DIRECTION OUTPUT ;
    USE SIGNAL ;
    PORT
      LAYER M4 ;
        RECT  14.982 34.704 15.066 34.728 ;
    END
  END q[107]
  PIN q[108]
    DIRECTION OUTPUT ;
    USE SIGNAL ;
    PORT
      LAYER M4 ;
        RECT  14.982 34.992 15.066 35.016 ;
    END
  END q[108]
  PIN q[109]
    DIRECTION OUTPUT ;
    USE SIGNAL ;
    PORT
      LAYER M4 ;
        RECT  14.982 35.28 15.066 35.304 ;
    END
  END q[109]
  PIN q[10]
    DIRECTION OUTPUT ;
    USE SIGNAL ;
    PORT
      LAYER M4 ;
        RECT  14.982 8.112 15.066 8.136 ;
    END
  END q[10]
  PIN q[110]
    DIRECTION OUTPUT ;
    USE SIGNAL ;
    PORT
      LAYER M4 ;
        RECT  14.982 35.52 15.066 35.544 ;
    END
  END q[110]
  PIN q[111]
    DIRECTION OUTPUT ;
    USE SIGNAL ;
    PORT
      LAYER M4 ;
        RECT  14.982 35.808 15.066 35.832 ;
    END
  END q[111]
  PIN q[112]
    DIRECTION OUTPUT ;
    USE SIGNAL ;
    PORT
      LAYER M4 ;
        RECT  14.982 36.096 15.066 36.12 ;
    END
  END q[112]
  PIN q[113]
    DIRECTION OUTPUT ;
    USE SIGNAL ;
    PORT
      LAYER M4 ;
        RECT  14.982 36.384 15.066 36.408 ;
    END
  END q[113]
  PIN q[114]
    DIRECTION OUTPUT ;
    USE SIGNAL ;
    PORT
      LAYER M4 ;
        RECT  14.982 36.624 15.066 36.648 ;
    END
  END q[114]
  PIN q[115]
    DIRECTION OUTPUT ;
    USE SIGNAL ;
    PORT
      LAYER M4 ;
        RECT  14.982 36.912 15.066 36.936 ;
    END
  END q[115]
  PIN q[116]
    DIRECTION OUTPUT ;
    USE SIGNAL ;
    PORT
      LAYER M4 ;
        RECT  14.982 37.2 15.066 37.224 ;
    END
  END q[116]
  PIN q[117]
    DIRECTION OUTPUT ;
    USE SIGNAL ;
    PORT
      LAYER M4 ;
        RECT  14.982 37.44 15.066 37.464 ;
    END
  END q[117]
  PIN q[118]
    DIRECTION OUTPUT ;
    USE SIGNAL ;
    PORT
      LAYER M4 ;
        RECT  14.982 37.728 15.066 37.752 ;
    END
  END q[118]
  PIN q[119]
    DIRECTION OUTPUT ;
    USE SIGNAL ;
    PORT
      LAYER M4 ;
        RECT  14.982 38.016 15.066 38.04 ;
    END
  END q[119]
  PIN q[11]
    DIRECTION OUTPUT ;
    USE SIGNAL ;
    PORT
      LAYER M4 ;
        RECT  14.982 8.4 15.066 8.424 ;
    END
  END q[11]
  PIN q[120]
    DIRECTION OUTPUT ;
    USE SIGNAL ;
    PORT
      LAYER M4 ;
        RECT  14.982 38.304 15.066 38.328 ;
    END
  END q[120]
  PIN q[121]
    DIRECTION OUTPUT ;
    USE SIGNAL ;
    PORT
      LAYER M4 ;
        RECT  14.982 38.544 15.066 38.568 ;
    END
  END q[121]
  PIN q[122]
    DIRECTION OUTPUT ;
    USE SIGNAL ;
    PORT
      LAYER M4 ;
        RECT  14.982 38.832 15.066 38.856 ;
    END
  END q[122]
  PIN q[123]
    DIRECTION OUTPUT ;
    USE SIGNAL ;
    PORT
      LAYER M4 ;
        RECT  14.982 39.12 15.066 39.144 ;
    END
  END q[123]
  PIN q[124]
    DIRECTION OUTPUT ;
    USE SIGNAL ;
    PORT
      LAYER M4 ;
        RECT  14.982 39.36 15.066 39.384 ;
    END
  END q[124]
  PIN q[125]
    DIRECTION OUTPUT ;
    USE SIGNAL ;
    PORT
      LAYER M4 ;
        RECT  14.982 39.648 15.066 39.672 ;
    END
  END q[125]
  PIN q[126]
    DIRECTION OUTPUT ;
    USE SIGNAL ;
    PORT
      LAYER M4 ;
        RECT  14.982 39.936 15.066 39.96 ;
    END
  END q[126]
  PIN q[127]
    DIRECTION OUTPUT ;
    USE SIGNAL ;
    PORT
      LAYER M4 ;
        RECT  14.982 40.224 15.066 40.248 ;
    END
  END q[127]
  PIN q[128]
    DIRECTION OUTPUT ;
    USE SIGNAL ;
    PORT
      LAYER M4 ;
        RECT  14.982 40.464 15.066 40.488 ;
    END
  END q[128]
  PIN q[129]
    DIRECTION OUTPUT ;
    USE SIGNAL ;
    PORT
      LAYER M4 ;
        RECT  14.982 40.752 15.066 40.776 ;
    END
  END q[129]
  PIN q[12]
    DIRECTION OUTPUT ;
    USE SIGNAL ;
    PORT
      LAYER M4 ;
        RECT  14.982 8.688 15.066 8.712 ;
    END
  END q[12]
  PIN q[130]
    DIRECTION OUTPUT ;
    USE SIGNAL ;
    PORT
      LAYER M4 ;
        RECT  14.982 41.04 15.066 41.064 ;
    END
  END q[130]
  PIN q[131]
    DIRECTION OUTPUT ;
    USE SIGNAL ;
    PORT
      LAYER M4 ;
        RECT  14.982 41.28 15.066 41.304 ;
    END
  END q[131]
  PIN q[132]
    DIRECTION OUTPUT ;
    USE SIGNAL ;
    PORT
      LAYER M4 ;
        RECT  14.982 41.568 15.066 41.592 ;
    END
  END q[132]
  PIN q[133]
    DIRECTION OUTPUT ;
    USE SIGNAL ;
    PORT
      LAYER M4 ;
        RECT  14.982 41.856 15.066 41.88 ;
    END
  END q[133]
  PIN q[134]
    DIRECTION OUTPUT ;
    USE SIGNAL ;
    PORT
      LAYER M4 ;
        RECT  14.982 42.096 15.066 42.12 ;
    END
  END q[134]
  PIN q[135]
    DIRECTION OUTPUT ;
    USE SIGNAL ;
    PORT
      LAYER M4 ;
        RECT  14.982 42.384 15.066 42.408 ;
    END
  END q[135]
  PIN q[136]
    DIRECTION OUTPUT ;
    USE SIGNAL ;
    PORT
      LAYER M4 ;
        RECT  14.982 42.672 15.066 42.696 ;
    END
  END q[136]
  PIN q[137]
    DIRECTION OUTPUT ;
    USE SIGNAL ;
    PORT
      LAYER M4 ;
        RECT  14.982 42.96 15.066 42.984 ;
    END
  END q[137]
  PIN q[138]
    DIRECTION OUTPUT ;
    USE SIGNAL ;
    PORT
      LAYER M4 ;
        RECT  14.982 43.2 15.066 43.224 ;
    END
  END q[138]
  PIN q[139]
    DIRECTION OUTPUT ;
    USE SIGNAL ;
    PORT
      LAYER M4 ;
        RECT  14.982 43.488 15.066 43.512 ;
    END
  END q[139]
  PIN q[13]
    DIRECTION OUTPUT ;
    USE SIGNAL ;
    PORT
      LAYER M4 ;
        RECT  14.982 8.928 15.066 8.952 ;
    END
  END q[13]
  PIN q[140]
    DIRECTION OUTPUT ;
    USE SIGNAL ;
    PORT
      LAYER M4 ;
        RECT  14.982 43.776 15.066 43.8 ;
    END
  END q[140]
  PIN q[141]
    DIRECTION OUTPUT ;
    USE SIGNAL ;
    PORT
      LAYER M4 ;
        RECT  14.982 44.016 15.066 44.04 ;
    END
  END q[141]
  PIN q[142]
    DIRECTION OUTPUT ;
    USE SIGNAL ;
    PORT
      LAYER M4 ;
        RECT  14.982 44.304 15.066 44.328 ;
    END
  END q[142]
  PIN q[143]
    DIRECTION OUTPUT ;
    USE SIGNAL ;
    PORT
      LAYER M4 ;
        RECT  14.982 44.592 15.066 44.616 ;
    END
  END q[143]
  PIN q[144]
    DIRECTION OUTPUT ;
    USE SIGNAL ;
    PORT
      LAYER M4 ;
        RECT  14.982 44.88 15.066 44.904 ;
    END
  END q[144]
  PIN q[145]
    DIRECTION OUTPUT ;
    USE SIGNAL ;
    PORT
      LAYER M4 ;
        RECT  14.982 45.12 15.066 45.144 ;
    END
  END q[145]
  PIN q[146]
    DIRECTION OUTPUT ;
    USE SIGNAL ;
    PORT
      LAYER M4 ;
        RECT  14.982 45.408 15.066 45.432 ;
    END
  END q[146]
  PIN q[147]
    DIRECTION OUTPUT ;
    USE SIGNAL ;
    PORT
      LAYER M4 ;
        RECT  14.982 45.696 15.066 45.72 ;
    END
  END q[147]
  PIN q[148]
    DIRECTION OUTPUT ;
    USE SIGNAL ;
    PORT
      LAYER M4 ;
        RECT  14.982 45.936 15.066 45.96 ;
    END
  END q[148]
  PIN q[149]
    DIRECTION OUTPUT ;
    USE SIGNAL ;
    PORT
      LAYER M4 ;
        RECT  14.982 46.224 15.066 46.248 ;
    END
  END q[149]
  PIN q[14]
    DIRECTION OUTPUT ;
    USE SIGNAL ;
    PORT
      LAYER M4 ;
        RECT  14.982 9.216 15.066 9.24 ;
    END
  END q[14]
  PIN q[150]
    DIRECTION OUTPUT ;
    USE SIGNAL ;
    PORT
      LAYER M4 ;
        RECT  14.982 46.512 15.066 46.536 ;
    END
  END q[150]
  PIN q[151]
    DIRECTION OUTPUT ;
    USE SIGNAL ;
    PORT
      LAYER M4 ;
        RECT  14.982 46.8 15.066 46.824 ;
    END
  END q[151]
  PIN q[152]
    DIRECTION OUTPUT ;
    USE SIGNAL ;
    PORT
      LAYER M4 ;
        RECT  14.982 47.04 15.066 47.064 ;
    END
  END q[152]
  PIN q[153]
    DIRECTION OUTPUT ;
    USE SIGNAL ;
    PORT
      LAYER M4 ;
        RECT  14.982 47.328 15.066 47.352 ;
    END
  END q[153]
  PIN q[154]
    DIRECTION OUTPUT ;
    USE SIGNAL ;
    PORT
      LAYER M4 ;
        RECT  14.982 47.616 15.066 47.64 ;
    END
  END q[154]
  PIN q[155]
    DIRECTION OUTPUT ;
    USE SIGNAL ;
    PORT
      LAYER M4 ;
        RECT  14.982 47.856 15.066 47.88 ;
    END
  END q[155]
  PIN q[156]
    DIRECTION OUTPUT ;
    USE SIGNAL ;
    PORT
      LAYER M4 ;
        RECT  14.982 48.144 15.066 48.168 ;
    END
  END q[156]
  PIN q[157]
    DIRECTION OUTPUT ;
    USE SIGNAL ;
    PORT
      LAYER M4 ;
        RECT  14.982 48.432 15.066 48.456 ;
    END
  END q[157]
  PIN q[158]
    DIRECTION OUTPUT ;
    USE SIGNAL ;
    PORT
      LAYER M4 ;
        RECT  14.982 48.72 15.066 48.744 ;
    END
  END q[158]
  PIN q[159]
    DIRECTION OUTPUT ;
    USE SIGNAL ;
    PORT
      LAYER M4 ;
        RECT  14.982 48.96 15.066 48.984 ;
    END
  END q[159]
  PIN q[15]
    DIRECTION OUTPUT ;
    USE SIGNAL ;
    PORT
      LAYER M4 ;
        RECT  14.982 9.504 15.066 9.528 ;
    END
  END q[15]
  PIN q[160]
    DIRECTION OUTPUT ;
    USE SIGNAL ;
    PORT
      LAYER M4 ;
        RECT  14.982 49.248 15.066 49.272 ;
    END
  END q[160]
  PIN q[161]
    DIRECTION OUTPUT ;
    USE SIGNAL ;
    PORT
      LAYER M4 ;
        RECT  14.982 49.536 15.066 49.56 ;
    END
  END q[161]
  PIN q[162]
    DIRECTION OUTPUT ;
    USE SIGNAL ;
    PORT
      LAYER M4 ;
        RECT  14.982 49.776 15.066 49.8 ;
    END
  END q[162]
  PIN q[163]
    DIRECTION OUTPUT ;
    USE SIGNAL ;
    PORT
      LAYER M4 ;
        RECT  14.982 50.064 15.066 50.088 ;
    END
  END q[163]
  PIN q[164]
    DIRECTION OUTPUT ;
    USE SIGNAL ;
    PORT
      LAYER M4 ;
        RECT  14.982 50.352 15.066 50.376 ;
    END
  END q[164]
  PIN q[165]
    DIRECTION OUTPUT ;
    USE SIGNAL ;
    PORT
      LAYER M4 ;
        RECT  14.982 50.64 15.066 50.664 ;
    END
  END q[165]
  PIN q[166]
    DIRECTION OUTPUT ;
    USE SIGNAL ;
    PORT
      LAYER M4 ;
        RECT  14.982 50.88 15.066 50.904 ;
    END
  END q[166]
  PIN q[167]
    DIRECTION OUTPUT ;
    USE SIGNAL ;
    PORT
      LAYER M4 ;
        RECT  14.982 51.168 15.066 51.192 ;
    END
  END q[167]
  PIN q[168]
    DIRECTION OUTPUT ;
    USE SIGNAL ;
    PORT
      LAYER M4 ;
        RECT  14.982 51.456 15.066 51.48 ;
    END
  END q[168]
  PIN q[169]
    DIRECTION OUTPUT ;
    USE SIGNAL ;
    PORT
      LAYER M4 ;
        RECT  14.982 51.696 15.066 51.72 ;
    END
  END q[169]
  PIN q[16]
    DIRECTION OUTPUT ;
    USE SIGNAL ;
    PORT
      LAYER M4 ;
        RECT  14.982 9.792 15.066 9.816 ;
    END
  END q[16]
  PIN q[170]
    DIRECTION OUTPUT ;
    USE SIGNAL ;
    PORT
      LAYER M4 ;
        RECT  14.982 51.984 15.066 52.008 ;
    END
  END q[170]
  PIN q[171]
    DIRECTION OUTPUT ;
    USE SIGNAL ;
    PORT
      LAYER M4 ;
        RECT  14.982 52.272 15.066 52.296 ;
    END
  END q[171]
  PIN q[172]
    DIRECTION OUTPUT ;
    USE SIGNAL ;
    PORT
      LAYER M4 ;
        RECT  14.982 52.512 15.066 52.536 ;
    END
  END q[172]
  PIN q[173]
    DIRECTION OUTPUT ;
    USE SIGNAL ;
    PORT
      LAYER M4 ;
        RECT  14.982 52.8 15.066 52.824 ;
    END
  END q[173]
  PIN q[174]
    DIRECTION OUTPUT ;
    USE SIGNAL ;
    PORT
      LAYER M4 ;
        RECT  14.982 53.088 15.066 53.112 ;
    END
  END q[174]
  PIN q[175]
    DIRECTION OUTPUT ;
    USE SIGNAL ;
    PORT
      LAYER M4 ;
        RECT  14.982 53.376 15.066 53.4 ;
    END
  END q[175]
  PIN q[176]
    DIRECTION OUTPUT ;
    USE SIGNAL ;
    PORT
      LAYER M4 ;
        RECT  14.982 53.616 15.066 53.64 ;
    END
  END q[176]
  PIN q[177]
    DIRECTION OUTPUT ;
    USE SIGNAL ;
    PORT
      LAYER M4 ;
        RECT  14.982 53.904 15.066 53.928 ;
    END
  END q[177]
  PIN q[178]
    DIRECTION OUTPUT ;
    USE SIGNAL ;
    PORT
      LAYER M4 ;
        RECT  14.982 54.192 15.066 54.216 ;
    END
  END q[178]
  PIN q[179]
    DIRECTION OUTPUT ;
    USE SIGNAL ;
    PORT
      LAYER M4 ;
        RECT  14.982 54.432 15.066 54.456 ;
    END
  END q[179]
  PIN q[17]
    DIRECTION OUTPUT ;
    USE SIGNAL ;
    PORT
      LAYER M4 ;
        RECT  14.982 10.032 15.066 10.056 ;
    END
  END q[17]
  PIN q[180]
    DIRECTION OUTPUT ;
    USE SIGNAL ;
    PORT
      LAYER M4 ;
        RECT  14.982 54.72 15.066 54.744 ;
    END
  END q[180]
  PIN q[181]
    DIRECTION OUTPUT ;
    USE SIGNAL ;
    PORT
      LAYER M4 ;
        RECT  14.982 55.008 15.066 55.032 ;
    END
  END q[181]
  PIN q[182]
    DIRECTION OUTPUT ;
    USE SIGNAL ;
    PORT
      LAYER M4 ;
        RECT  14.982 55.296 15.066 55.32 ;
    END
  END q[182]
  PIN q[183]
    DIRECTION OUTPUT ;
    USE SIGNAL ;
    PORT
      LAYER M4 ;
        RECT  14.982 55.536 15.066 55.56 ;
    END
  END q[183]
  PIN q[184]
    DIRECTION OUTPUT ;
    USE SIGNAL ;
    PORT
      LAYER M4 ;
        RECT  14.982 55.824 15.066 55.848 ;
    END
  END q[184]
  PIN q[185]
    DIRECTION OUTPUT ;
    USE SIGNAL ;
    PORT
      LAYER M4 ;
        RECT  14.982 56.112 15.066 56.136 ;
    END
  END q[185]
  PIN q[186]
    DIRECTION OUTPUT ;
    USE SIGNAL ;
    PORT
      LAYER M4 ;
        RECT  14.982 56.352 15.066 56.376 ;
    END
  END q[186]
  PIN q[187]
    DIRECTION OUTPUT ;
    USE SIGNAL ;
    PORT
      LAYER M4 ;
        RECT  14.982 56.64 15.066 56.664 ;
    END
  END q[187]
  PIN q[188]
    DIRECTION OUTPUT ;
    USE SIGNAL ;
    PORT
      LAYER M4 ;
        RECT  14.982 56.928 15.066 56.952 ;
    END
  END q[188]
  PIN q[189]
    DIRECTION OUTPUT ;
    USE SIGNAL ;
    PORT
      LAYER M4 ;
        RECT  14.982 57.216 15.066 57.24 ;
    END
  END q[189]
  PIN q[18]
    DIRECTION OUTPUT ;
    USE SIGNAL ;
    PORT
      LAYER M4 ;
        RECT  14.982 10.32 15.066 10.344 ;
    END
  END q[18]
  PIN q[190]
    DIRECTION OUTPUT ;
    USE SIGNAL ;
    PORT
      LAYER M4 ;
        RECT  14.982 57.456 15.066 57.48 ;
    END
  END q[190]
  PIN q[191]
    DIRECTION OUTPUT ;
    USE SIGNAL ;
    PORT
      LAYER M4 ;
        RECT  14.982 57.744 15.066 57.768 ;
    END
  END q[191]
  PIN q[192]
    DIRECTION OUTPUT ;
    USE SIGNAL ;
    PORT
      LAYER M4 ;
        RECT  14.982 58.032 15.066 58.056 ;
    END
  END q[192]
  PIN q[193]
    DIRECTION OUTPUT ;
    USE SIGNAL ;
    PORT
      LAYER M4 ;
        RECT  14.982 58.272 15.066 58.296 ;
    END
  END q[193]
  PIN q[194]
    DIRECTION OUTPUT ;
    USE SIGNAL ;
    PORT
      LAYER M4 ;
        RECT  14.982 58.56 15.066 58.584 ;
    END
  END q[194]
  PIN q[195]
    DIRECTION OUTPUT ;
    USE SIGNAL ;
    PORT
      LAYER M4 ;
        RECT  14.982 58.848 15.066 58.872 ;
    END
  END q[195]
  PIN q[196]
    DIRECTION OUTPUT ;
    USE SIGNAL ;
    PORT
      LAYER M4 ;
        RECT  14.982 59.136 15.066 59.16 ;
    END
  END q[196]
  PIN q[197]
    DIRECTION OUTPUT ;
    USE SIGNAL ;
    PORT
      LAYER M4 ;
        RECT  14.982 59.376 15.066 59.4 ;
    END
  END q[197]
  PIN q[19]
    DIRECTION OUTPUT ;
    USE SIGNAL ;
    PORT
      LAYER M4 ;
        RECT  14.982 10.608 15.066 10.632 ;
    END
  END q[19]
  PIN q[1]
    DIRECTION OUTPUT ;
    USE SIGNAL ;
    PORT
      LAYER M4 ;
        RECT  14.982 5.664 15.066 5.688 ;
    END
  END q[1]
  PIN q[20]
    DIRECTION OUTPUT ;
    USE SIGNAL ;
    PORT
      LAYER M4 ;
        RECT  14.982 10.848 15.066 10.872 ;
    END
  END q[20]
  PIN q[21]
    DIRECTION OUTPUT ;
    USE SIGNAL ;
    PORT
      LAYER M4 ;
        RECT  14.982 11.136 15.066 11.16 ;
    END
  END q[21]
  PIN q[22]
    DIRECTION OUTPUT ;
    USE SIGNAL ;
    PORT
      LAYER M4 ;
        RECT  14.982 11.424 15.066 11.448 ;
    END
  END q[22]
  PIN q[23]
    DIRECTION OUTPUT ;
    USE SIGNAL ;
    PORT
      LAYER M4 ;
        RECT  14.982 11.712 15.066 11.736 ;
    END
  END q[23]
  PIN q[24]
    DIRECTION OUTPUT ;
    USE SIGNAL ;
    PORT
      LAYER M4 ;
        RECT  14.982 11.952 15.066 11.976 ;
    END
  END q[24]
  PIN q[25]
    DIRECTION OUTPUT ;
    USE SIGNAL ;
    PORT
      LAYER M4 ;
        RECT  14.982 12.24 15.066 12.264 ;
    END
  END q[25]
  PIN q[26]
    DIRECTION OUTPUT ;
    USE SIGNAL ;
    PORT
      LAYER M4 ;
        RECT  14.982 12.528 15.066 12.552 ;
    END
  END q[26]
  PIN q[27]
    DIRECTION OUTPUT ;
    USE SIGNAL ;
    PORT
      LAYER M4 ;
        RECT  14.982 12.768 15.066 12.792 ;
    END
  END q[27]
  PIN q[28]
    DIRECTION OUTPUT ;
    USE SIGNAL ;
    PORT
      LAYER M4 ;
        RECT  14.982 13.056 15.066 13.08 ;
    END
  END q[28]
  PIN q[29]
    DIRECTION OUTPUT ;
    USE SIGNAL ;
    PORT
      LAYER M4 ;
        RECT  14.982 13.344 15.066 13.368 ;
    END
  END q[29]
  PIN q[2]
    DIRECTION OUTPUT ;
    USE SIGNAL ;
    PORT
      LAYER M4 ;
        RECT  14.982 5.952 15.066 5.976 ;
    END
  END q[2]
  PIN q[30]
    DIRECTION OUTPUT ;
    USE SIGNAL ;
    PORT
      LAYER M4 ;
        RECT  14.982 13.632 15.066 13.656 ;
    END
  END q[30]
  PIN q[31]
    DIRECTION OUTPUT ;
    USE SIGNAL ;
    PORT
      LAYER M4 ;
        RECT  14.982 13.872 15.066 13.896 ;
    END
  END q[31]
  PIN q[32]
    DIRECTION OUTPUT ;
    USE SIGNAL ;
    PORT
      LAYER M4 ;
        RECT  14.982 14.16 15.066 14.184 ;
    END
  END q[32]
  PIN q[33]
    DIRECTION OUTPUT ;
    USE SIGNAL ;
    PORT
      LAYER M4 ;
        RECT  14.982 14.448 15.066 14.472 ;
    END
  END q[33]
  PIN q[34]
    DIRECTION OUTPUT ;
    USE SIGNAL ;
    PORT
      LAYER M4 ;
        RECT  14.982 14.688 15.066 14.712 ;
    END
  END q[34]
  PIN q[35]
    DIRECTION OUTPUT ;
    USE SIGNAL ;
    PORT
      LAYER M4 ;
        RECT  14.982 14.976 15.066 15 ;
    END
  END q[35]
  PIN q[36]
    DIRECTION OUTPUT ;
    USE SIGNAL ;
    PORT
      LAYER M4 ;
        RECT  14.982 15.264 15.066 15.288 ;
    END
  END q[36]
  PIN q[37]
    DIRECTION OUTPUT ;
    USE SIGNAL ;
    PORT
      LAYER M4 ;
        RECT  14.982 15.552 15.066 15.576 ;
    END
  END q[37]
  PIN q[38]
    DIRECTION OUTPUT ;
    USE SIGNAL ;
    PORT
      LAYER M4 ;
        RECT  14.982 15.792 15.066 15.816 ;
    END
  END q[38]
  PIN q[39]
    DIRECTION OUTPUT ;
    USE SIGNAL ;
    PORT
      LAYER M4 ;
        RECT  14.982 16.08 15.066 16.104 ;
    END
  END q[39]
  PIN q[3]
    DIRECTION OUTPUT ;
    USE SIGNAL ;
    PORT
      LAYER M4 ;
        RECT  14.982 6.192 15.066 6.216 ;
    END
  END q[3]
  PIN q[40]
    DIRECTION OUTPUT ;
    USE SIGNAL ;
    PORT
      LAYER M4 ;
        RECT  14.982 16.368 15.066 16.392 ;
    END
  END q[40]
  PIN q[41]
    DIRECTION OUTPUT ;
    USE SIGNAL ;
    PORT
      LAYER M4 ;
        RECT  14.982 16.608 15.066 16.632 ;
    END
  END q[41]
  PIN q[42]
    DIRECTION OUTPUT ;
    USE SIGNAL ;
    PORT
      LAYER M4 ;
        RECT  14.982 16.896 15.066 16.92 ;
    END
  END q[42]
  PIN q[43]
    DIRECTION OUTPUT ;
    USE SIGNAL ;
    PORT
      LAYER M4 ;
        RECT  14.982 17.184 15.066 17.208 ;
    END
  END q[43]
  PIN q[44]
    DIRECTION OUTPUT ;
    USE SIGNAL ;
    PORT
      LAYER M4 ;
        RECT  14.982 17.472 15.066 17.496 ;
    END
  END q[44]
  PIN q[45]
    DIRECTION OUTPUT ;
    USE SIGNAL ;
    PORT
      LAYER M4 ;
        RECT  14.982 17.712 15.066 17.736 ;
    END
  END q[45]
  PIN q[46]
    DIRECTION OUTPUT ;
    USE SIGNAL ;
    PORT
      LAYER M4 ;
        RECT  14.982 18 15.066 18.024 ;
    END
  END q[46]
  PIN q[47]
    DIRECTION OUTPUT ;
    USE SIGNAL ;
    PORT
      LAYER M4 ;
        RECT  14.982 18.288 15.066 18.312 ;
    END
  END q[47]
  PIN q[48]
    DIRECTION OUTPUT ;
    USE SIGNAL ;
    PORT
      LAYER M4 ;
        RECT  14.982 18.528 15.066 18.552 ;
    END
  END q[48]
  PIN q[49]
    DIRECTION OUTPUT ;
    USE SIGNAL ;
    PORT
      LAYER M4 ;
        RECT  14.982 18.816 15.066 18.84 ;
    END
  END q[49]
  PIN q[4]
    DIRECTION OUTPUT ;
    USE SIGNAL ;
    PORT
      LAYER M4 ;
        RECT  14.982 6.48 15.066 6.504 ;
    END
  END q[4]
  PIN q[50]
    DIRECTION OUTPUT ;
    USE SIGNAL ;
    PORT
      LAYER M4 ;
        RECT  14.982 19.104 15.066 19.128 ;
    END
  END q[50]
  PIN q[51]
    DIRECTION OUTPUT ;
    USE SIGNAL ;
    PORT
      LAYER M4 ;
        RECT  14.982 19.344 15.066 19.368 ;
    END
  END q[51]
  PIN q[52]
    DIRECTION OUTPUT ;
    USE SIGNAL ;
    PORT
      LAYER M4 ;
        RECT  14.982 19.632 15.066 19.656 ;
    END
  END q[52]
  PIN q[53]
    DIRECTION OUTPUT ;
    USE SIGNAL ;
    PORT
      LAYER M4 ;
        RECT  14.982 19.92 15.066 19.944 ;
    END
  END q[53]
  PIN q[54]
    DIRECTION OUTPUT ;
    USE SIGNAL ;
    PORT
      LAYER M4 ;
        RECT  14.982 20.208 15.066 20.232 ;
    END
  END q[54]
  PIN q[55]
    DIRECTION OUTPUT ;
    USE SIGNAL ;
    PORT
      LAYER M4 ;
        RECT  14.982 20.448 15.066 20.472 ;
    END
  END q[55]
  PIN q[56]
    DIRECTION OUTPUT ;
    USE SIGNAL ;
    PORT
      LAYER M4 ;
        RECT  14.982 20.736 15.066 20.76 ;
    END
  END q[56]
  PIN q[57]
    DIRECTION OUTPUT ;
    USE SIGNAL ;
    PORT
      LAYER M4 ;
        RECT  14.982 21.024 15.066 21.048 ;
    END
  END q[57]
  PIN q[58]
    DIRECTION OUTPUT ;
    USE SIGNAL ;
    PORT
      LAYER M4 ;
        RECT  14.982 21.264 15.066 21.288 ;
    END
  END q[58]
  PIN q[59]
    DIRECTION OUTPUT ;
    USE SIGNAL ;
    PORT
      LAYER M4 ;
        RECT  14.982 21.552 15.066 21.576 ;
    END
  END q[59]
  PIN q[5]
    DIRECTION OUTPUT ;
    USE SIGNAL ;
    PORT
      LAYER M4 ;
        RECT  14.982 6.768 15.066 6.792 ;
    END
  END q[5]
  PIN q[60]
    DIRECTION OUTPUT ;
    USE SIGNAL ;
    PORT
      LAYER M4 ;
        RECT  14.982 21.84 15.066 21.864 ;
    END
  END q[60]
  PIN q[61]
    DIRECTION OUTPUT ;
    USE SIGNAL ;
    PORT
      LAYER M4 ;
        RECT  14.982 22.128 15.066 22.152 ;
    END
  END q[61]
  PIN q[62]
    DIRECTION OUTPUT ;
    USE SIGNAL ;
    PORT
      LAYER M4 ;
        RECT  14.982 22.368 15.066 22.392 ;
    END
  END q[62]
  PIN q[63]
    DIRECTION OUTPUT ;
    USE SIGNAL ;
    PORT
      LAYER M4 ;
        RECT  14.982 22.656 15.066 22.68 ;
    END
  END q[63]
  PIN q[64]
    DIRECTION OUTPUT ;
    USE SIGNAL ;
    PORT
      LAYER M4 ;
        RECT  14.982 22.944 15.066 22.968 ;
    END
  END q[64]
  PIN q[65]
    DIRECTION OUTPUT ;
    USE SIGNAL ;
    PORT
      LAYER M4 ;
        RECT  14.982 23.184 15.066 23.208 ;
    END
  END q[65]
  PIN q[66]
    DIRECTION OUTPUT ;
    USE SIGNAL ;
    PORT
      LAYER M4 ;
        RECT  14.982 23.472 15.066 23.496 ;
    END
  END q[66]
  PIN q[67]
    DIRECTION OUTPUT ;
    USE SIGNAL ;
    PORT
      LAYER M4 ;
        RECT  14.982 23.76 15.066 23.784 ;
    END
  END q[67]
  PIN q[68]
    DIRECTION OUTPUT ;
    USE SIGNAL ;
    PORT
      LAYER M4 ;
        RECT  14.982 24.048 15.066 24.072 ;
    END
  END q[68]
  PIN q[69]
    DIRECTION OUTPUT ;
    USE SIGNAL ;
    PORT
      LAYER M4 ;
        RECT  14.982 24.288 15.066 24.312 ;
    END
  END q[69]
  PIN q[6]
    DIRECTION OUTPUT ;
    USE SIGNAL ;
    PORT
      LAYER M4 ;
        RECT  14.982 7.056 15.066 7.08 ;
    END
  END q[6]
  PIN q[70]
    DIRECTION OUTPUT ;
    USE SIGNAL ;
    PORT
      LAYER M4 ;
        RECT  14.982 24.576 15.066 24.6 ;
    END
  END q[70]
  PIN q[71]
    DIRECTION OUTPUT ;
    USE SIGNAL ;
    PORT
      LAYER M4 ;
        RECT  14.982 24.864 15.066 24.888 ;
    END
  END q[71]
  PIN q[72]
    DIRECTION OUTPUT ;
    USE SIGNAL ;
    PORT
      LAYER M4 ;
        RECT  14.982 25.104 15.066 25.128 ;
    END
  END q[72]
  PIN q[73]
    DIRECTION OUTPUT ;
    USE SIGNAL ;
    PORT
      LAYER M4 ;
        RECT  14.982 25.392 15.066 25.416 ;
    END
  END q[73]
  PIN q[74]
    DIRECTION OUTPUT ;
    USE SIGNAL ;
    PORT
      LAYER M4 ;
        RECT  14.982 25.68 15.066 25.704 ;
    END
  END q[74]
  PIN q[75]
    DIRECTION OUTPUT ;
    USE SIGNAL ;
    PORT
      LAYER M4 ;
        RECT  14.982 25.968 15.066 25.992 ;
    END
  END q[75]
  PIN q[76]
    DIRECTION OUTPUT ;
    USE SIGNAL ;
    PORT
      LAYER M4 ;
        RECT  14.982 26.208 15.066 26.232 ;
    END
  END q[76]
  PIN q[77]
    DIRECTION OUTPUT ;
    USE SIGNAL ;
    PORT
      LAYER M4 ;
        RECT  14.982 26.496 15.066 26.52 ;
    END
  END q[77]
  PIN q[78]
    DIRECTION OUTPUT ;
    USE SIGNAL ;
    PORT
      LAYER M4 ;
        RECT  14.982 26.784 15.066 26.808 ;
    END
  END q[78]
  PIN q[79]
    DIRECTION OUTPUT ;
    USE SIGNAL ;
    PORT
      LAYER M4 ;
        RECT  14.982 27.024 15.066 27.048 ;
    END
  END q[79]
  PIN q[7]
    DIRECTION OUTPUT ;
    USE SIGNAL ;
    PORT
      LAYER M4 ;
        RECT  14.982 7.296 15.066 7.32 ;
    END
  END q[7]
  PIN q[80]
    DIRECTION OUTPUT ;
    USE SIGNAL ;
    PORT
      LAYER M4 ;
        RECT  14.982 27.312 15.066 27.336 ;
    END
  END q[80]
  PIN q[81]
    DIRECTION OUTPUT ;
    USE SIGNAL ;
    PORT
      LAYER M4 ;
        RECT  14.982 27.6 15.066 27.624 ;
    END
  END q[81]
  PIN q[82]
    DIRECTION OUTPUT ;
    USE SIGNAL ;
    PORT
      LAYER M4 ;
        RECT  14.982 27.888 15.066 27.912 ;
    END
  END q[82]
  PIN q[83]
    DIRECTION OUTPUT ;
    USE SIGNAL ;
    PORT
      LAYER M4 ;
        RECT  14.982 28.128 15.066 28.152 ;
    END
  END q[83]
  PIN q[84]
    DIRECTION OUTPUT ;
    USE SIGNAL ;
    PORT
      LAYER M4 ;
        RECT  14.982 28.416 15.066 28.44 ;
    END
  END q[84]
  PIN q[85]
    DIRECTION OUTPUT ;
    USE SIGNAL ;
    PORT
      LAYER M4 ;
        RECT  14.982 28.704 15.066 28.728 ;
    END
  END q[85]
  PIN q[86]
    DIRECTION OUTPUT ;
    USE SIGNAL ;
    PORT
      LAYER M4 ;
        RECT  14.982 28.944 15.066 28.968 ;
    END
  END q[86]
  PIN q[87]
    DIRECTION OUTPUT ;
    USE SIGNAL ;
    PORT
      LAYER M4 ;
        RECT  14.982 29.232 15.066 29.256 ;
    END
  END q[87]
  PIN q[88]
    DIRECTION OUTPUT ;
    USE SIGNAL ;
    PORT
      LAYER M4 ;
        RECT  14.982 29.52 15.066 29.544 ;
    END
  END q[88]
  PIN q[89]
    DIRECTION OUTPUT ;
    USE SIGNAL ;
    PORT
      LAYER M4 ;
        RECT  14.982 29.76 15.066 29.784 ;
    END
  END q[89]
  PIN q[8]
    DIRECTION OUTPUT ;
    USE SIGNAL ;
    PORT
      LAYER M4 ;
        RECT  14.982 7.584 15.066 7.608 ;
    END
  END q[8]
  PIN q[90]
    DIRECTION OUTPUT ;
    USE SIGNAL ;
    PORT
      LAYER M4 ;
        RECT  14.982 30.048 15.066 30.072 ;
    END
  END q[90]
  PIN q[91]
    DIRECTION OUTPUT ;
    USE SIGNAL ;
    PORT
      LAYER M4 ;
        RECT  14.982 30.336 15.066 30.36 ;
    END
  END q[91]
  PIN q[92]
    DIRECTION OUTPUT ;
    USE SIGNAL ;
    PORT
      LAYER M4 ;
        RECT  14.982 30.624 15.066 30.648 ;
    END
  END q[92]
  PIN q[93]
    DIRECTION OUTPUT ;
    USE SIGNAL ;
    PORT
      LAYER M4 ;
        RECT  14.982 30.864 15.066 30.888 ;
    END
  END q[93]
  PIN q[94]
    DIRECTION OUTPUT ;
    USE SIGNAL ;
    PORT
      LAYER M4 ;
        RECT  14.982 31.152 15.066 31.176 ;
    END
  END q[94]
  PIN q[95]
    DIRECTION OUTPUT ;
    USE SIGNAL ;
    PORT
      LAYER M4 ;
        RECT  14.982 31.44 15.066 31.464 ;
    END
  END q[95]
  PIN q[96]
    DIRECTION OUTPUT ;
    USE SIGNAL ;
    PORT
      LAYER M4 ;
        RECT  14.982 31.68 15.066 31.704 ;
    END
  END q[96]
  PIN q[97]
    DIRECTION OUTPUT ;
    USE SIGNAL ;
    PORT
      LAYER M4 ;
        RECT  14.982 31.968 15.066 31.992 ;
    END
  END q[97]
  PIN q[98]
    DIRECTION OUTPUT ;
    USE SIGNAL ;
    PORT
      LAYER M4 ;
        RECT  14.982 32.256 15.066 32.28 ;
    END
  END q[98]
  PIN q[99]
    DIRECTION OUTPUT ;
    USE SIGNAL ;
    PORT
      LAYER M4 ;
        RECT  14.982 32.544 15.066 32.568 ;
    END
  END q[99]
  PIN q[9]
    DIRECTION OUTPUT ;
    USE SIGNAL ;
    PORT
      LAYER M4 ;
        RECT  14.982 7.872 15.066 7.896 ;
    END
  END q[9]
  PIN rst_n
    DIRECTION INPUT ;
    USE SIGNAL ;
    PORT
      LAYER M5 ;
        RECT  9.696 0.054 9.72 0.138 ;
    END
    PORT
      LAYER M5 ;
        RECT  9.696 0.08 9.72 0.563 ;
    END
  END rst_n
  PIN VDD
    DIRECTION INOUT ;
    USE POWER ;
    PORT
      LAYER M5 ;
        RECT  10.692 2.151 10.812 62.649 ;
        RECT  7.992 2.151 8.112 62.649 ;
        RECT  5.292 2.151 5.412 62.649 ;
        RECT  2.592 2.151 2.712 62.649 ;
    END
  END VDD
  PIN VSS
    DIRECTION INOUT ;
    USE GROUND ;
    PORT
      LAYER M5 ;
        RECT  10.5 2.137 10.62 62.663 ;
        RECT  7.8 2.137 7.92 62.663 ;
        RECT  5.1 2.137 5.22 62.663 ;
        RECT  2.4 2.137 2.52 62.663 ;
    END
  END VSS
  # OT_OBS_CLOSED layer=M5 d_um=1.536 added=26
  OBS
    LAYER RVTN ;
     RECT  2.16 2.16 12.96 2.295 ;
     RECT  2.16 2.565 12.96 2.835 ;
     RECT  2.16 3.105 12.96 3.375 ;
     RECT  2.16 3.645 12.96 3.915 ;
     RECT  2.16 4.185 12.96 4.455 ;
     RECT  2.16 4.725 12.96 4.995 ;
     RECT  2.16 5.265 12.96 5.535 ;
     RECT  2.16 5.805 12.96 6.075 ;
     RECT  2.16 6.345 12.96 6.615 ;
     RECT  2.16 6.885 12.96 7.155 ;
     RECT  2.16 7.425 12.96 7.695 ;
     RECT  2.16 7.965 12.96 8.235 ;
     RECT  2.16 8.505 12.96 8.775 ;
     RECT  2.16 9.045 12.96 9.315 ;
     RECT  2.16 9.585 12.96 9.855 ;
     RECT  2.16 10.125 12.96 10.395 ;
     RECT  2.16 10.665 12.96 10.935 ;
     RECT  2.16 11.205 12.96 11.475 ;
     RECT  2.16 11.745 12.96 12.015 ;
     RECT  2.16 12.285 12.96 12.555 ;
     RECT  2.16 12.825 12.96 13.095 ;
     RECT  2.16 13.365 12.96 13.635 ;
     RECT  2.16 13.905 12.96 14.175 ;
     RECT  2.16 14.445 12.96 14.715 ;
     RECT  2.16 14.985 12.96 15.255 ;
     RECT  2.16 15.525 12.96 15.795 ;
     RECT  2.16 16.065 12.96 16.335 ;
     RECT  2.16 16.605 12.96 16.875 ;
     RECT  2.16 17.145 12.96 17.415 ;
     RECT  2.16 17.685 12.96 17.955 ;
     RECT  2.16 18.225 12.96 18.495 ;
     RECT  2.16 18.765 12.96 19.035 ;
     RECT  2.16 19.305 12.96 19.575 ;
     RECT  2.16 19.845 12.96 20.115 ;
     RECT  2.16 20.385 12.96 20.655 ;
     RECT  2.16 20.925 12.96 21.195 ;
     RECT  2.16 21.465 12.96 21.735 ;
     RECT  2.16 22.005 12.96 22.275 ;
     RECT  2.16 22.545 12.96 22.815 ;
     RECT  2.16 23.085 12.96 23.355 ;
     RECT  2.16 23.625 12.96 23.895 ;
     RECT  2.16 24.165 12.96 24.435 ;
     RECT  2.16 24.705 12.96 24.975 ;
     RECT  2.16 25.245 12.96 25.515 ;
     RECT  2.16 25.785 12.96 26.055 ;
     RECT  2.16 26.325 12.96 26.595 ;
     RECT  2.16 26.865 12.96 27.135 ;
     RECT  2.16 27.405 12.96 27.675 ;
     RECT  2.16 27.945 12.96 28.215 ;
     RECT  2.16 28.485 12.96 28.755 ;
     RECT  2.16 29.025 12.96 29.295 ;
     RECT  2.16 29.565 12.96 29.835 ;
     RECT  2.16 30.105 12.96 30.375 ;
     RECT  2.16 30.645 12.96 30.915 ;
     RECT  2.16 31.185 12.96 31.455 ;
     RECT  2.16 31.725 12.96 31.995 ;
     RECT  2.16 32.265 12.96 32.535 ;
     RECT  2.16 32.805 12.96 33.075 ;
     RECT  2.16 33.345 12.96 33.615 ;
     RECT  2.16 33.885 12.96 34.155 ;
     RECT  2.16 34.425 12.96 34.695 ;
     RECT  2.16 34.965 12.96 35.235 ;
     RECT  2.16 35.505 12.96 35.775 ;
     RECT  2.16 36.045 12.96 36.315 ;
     RECT  2.16 36.585 12.96 36.855 ;
     RECT  2.16 37.125 12.96 37.395 ;
     RECT  2.16 37.665 12.96 37.935 ;
     RECT  2.16 38.205 12.96 38.475 ;
     RECT  2.16 38.745 12.96 39.015 ;
     RECT  2.16 39.285 12.96 39.555 ;
     RECT  2.16 39.825 12.96 40.095 ;
     RECT  2.16 40.365 12.96 40.635 ;
     RECT  2.16 40.905 12.96 41.175 ;
     RECT  2.16 41.445 12.96 41.715 ;
     RECT  2.16 41.985 12.96 42.255 ;
     RECT  2.16 42.525 12.96 42.795 ;
     RECT  2.16 43.065 12.96 43.335 ;
     RECT  2.16 43.605 12.96 43.875 ;
     RECT  2.16 44.145 12.96 44.415 ;
     RECT  2.16 44.685 12.96 44.955 ;
     RECT  2.16 45.225 12.96 45.495 ;
     RECT  2.16 45.765 12.96 46.035 ;
     RECT  2.16 46.305 12.96 46.575 ;
     RECT  2.16 46.845 12.96 47.115 ;
     RECT  2.16 47.385 12.96 47.655 ;
     RECT  2.16 47.925 12.96 48.195 ;
     RECT  2.16 48.465 12.96 48.735 ;
     RECT  2.16 49.005 12.96 49.275 ;
     RECT  2.16 49.545 12.96 49.815 ;
     RECT  2.16 50.085 12.96 50.355 ;
     RECT  2.16 50.625 12.96 50.895 ;
     RECT  2.16 51.165 12.96 51.435 ;
     RECT  2.16 51.705 12.96 51.975 ;
     RECT  2.16 52.245 12.96 52.515 ;
     RECT  2.16 52.785 12.96 53.055 ;
     RECT  2.16 53.325 12.96 53.595 ;
     RECT  2.16 53.865 12.96 54.135 ;
     RECT  2.16 54.405 12.96 54.675 ;
     RECT  2.16 54.945 12.96 55.215 ;
     RECT  2.16 55.485 12.96 55.755 ;
     RECT  2.16 56.025 12.96 56.295 ;
     RECT  2.16 56.565 12.96 56.835 ;
     RECT  2.16 57.105 12.96 57.375 ;
     RECT  2.16 57.645 12.96 57.915 ;
     RECT  2.16 58.185 12.96 58.455 ;
     RECT  2.16 58.725 12.96 58.995 ;
     RECT  2.16 59.265 12.96 59.535 ;
     RECT  2.16 59.805 12.96 60.075 ;
     RECT  2.16 60.345 12.96 60.615 ;
     RECT  2.16 60.885 12.96 61.155 ;
     RECT  2.16 61.425 12.96 61.695 ;
     RECT  2.16 61.965 12.96 62.235 ;
     RECT  2.16 62.505 12.96 62.64 ;
    LAYER RVTP ;
     RECT  2.16 2.295 12.96 2.565 ;
     RECT  2.16 2.835 12.96 3.105 ;
     RECT  2.16 3.375 12.96 3.645 ;
     RECT  2.16 3.915 12.96 4.185 ;
     RECT  2.16 4.455 12.96 4.725 ;
     RECT  2.16 4.995 12.96 5.265 ;
     RECT  2.16 5.535 12.96 5.805 ;
     RECT  2.16 6.075 12.96 6.345 ;
     RECT  2.16 6.615 12.96 6.885 ;
     RECT  2.16 7.155 12.96 7.425 ;
     RECT  2.16 7.695 12.96 7.965 ;
     RECT  2.16 8.235 12.96 8.505 ;
     RECT  2.16 8.775 12.96 9.045 ;
     RECT  2.16 9.315 12.96 9.585 ;
     RECT  2.16 9.855 12.96 10.125 ;
     RECT  2.16 10.395 12.96 10.665 ;
     RECT  2.16 10.935 12.96 11.205 ;
     RECT  2.16 11.475 12.96 11.745 ;
     RECT  2.16 12.015 12.96 12.285 ;
     RECT  2.16 12.555 12.96 12.825 ;
     RECT  2.16 13.095 12.96 13.365 ;
     RECT  2.16 13.635 12.96 13.905 ;
     RECT  2.16 14.175 12.96 14.445 ;
     RECT  2.16 14.715 12.96 14.985 ;
     RECT  2.16 15.255 12.96 15.525 ;
     RECT  2.16 15.795 12.96 16.065 ;
     RECT  2.16 16.335 12.96 16.605 ;
     RECT  2.16 16.875 12.96 17.145 ;
     RECT  2.16 17.415 12.96 17.685 ;
     RECT  2.16 17.955 12.96 18.225 ;
     RECT  2.16 18.495 12.96 18.765 ;
     RECT  2.16 19.035 12.96 19.305 ;
     RECT  2.16 19.575 12.96 19.845 ;
     RECT  2.16 20.115 12.96 20.385 ;
     RECT  2.16 20.655 12.96 20.925 ;
     RECT  2.16 21.195 12.96 21.465 ;
     RECT  2.16 21.735 12.96 22.005 ;
     RECT  2.16 22.275 12.96 22.545 ;
     RECT  2.16 22.815 12.96 23.085 ;
     RECT  2.16 23.355 12.96 23.625 ;
     RECT  2.16 23.895 12.96 24.165 ;
     RECT  2.16 24.435 12.96 24.705 ;
     RECT  2.16 24.975 12.96 25.245 ;
     RECT  2.16 25.515 12.96 25.785 ;
     RECT  2.16 26.055 12.96 26.325 ;
     RECT  2.16 26.595 12.96 26.865 ;
     RECT  2.16 27.135 12.96 27.405 ;
     RECT  2.16 27.675 12.96 27.945 ;
     RECT  2.16 28.215 12.96 28.485 ;
     RECT  2.16 28.755 12.96 29.025 ;
     RECT  2.16 29.295 12.96 29.565 ;
     RECT  2.16 29.835 12.96 30.105 ;
     RECT  2.16 30.375 12.96 30.645 ;
     RECT  2.16 30.915 12.96 31.185 ;
     RECT  2.16 31.455 12.96 31.725 ;
     RECT  2.16 31.995 12.96 32.265 ;
     RECT  2.16 32.535 12.96 32.805 ;
     RECT  2.16 33.075 12.96 33.345 ;
     RECT  2.16 33.615 12.96 33.885 ;
     RECT  2.16 34.155 12.96 34.425 ;
     RECT  2.16 34.695 12.96 34.965 ;
     RECT  2.16 35.235 12.96 35.505 ;
     RECT  2.16 35.775 12.96 36.045 ;
     RECT  2.16 36.315 12.96 36.585 ;
     RECT  2.16 36.855 12.96 37.125 ;
     RECT  2.16 37.395 12.96 37.665 ;
     RECT  2.16 37.935 12.96 38.205 ;
     RECT  2.16 38.475 12.96 38.745 ;
     RECT  2.16 39.015 12.96 39.285 ;
     RECT  2.16 39.555 12.96 39.825 ;
     RECT  2.16 40.095 12.96 40.365 ;
     RECT  2.16 40.635 12.96 40.905 ;
     RECT  2.16 41.175 12.96 41.445 ;
     RECT  2.16 41.715 12.96 41.985 ;
     RECT  2.16 42.255 12.96 42.525 ;
     RECT  2.16 42.795 12.96 43.065 ;
     RECT  2.16 43.335 12.96 43.605 ;
     RECT  2.16 43.875 12.96 44.145 ;
     RECT  2.16 44.415 12.96 44.685 ;
     RECT  2.16 44.955 12.96 45.225 ;
     RECT  2.16 45.495 12.96 45.765 ;
     RECT  2.16 46.035 12.96 46.305 ;
     RECT  2.16 46.575 12.96 46.845 ;
     RECT  2.16 47.115 12.96 47.385 ;
     RECT  2.16 47.655 12.96 47.925 ;
     RECT  2.16 48.195 12.96 48.465 ;
     RECT  2.16 48.735 12.96 49.005 ;
     RECT  2.16 49.275 12.96 49.545 ;
     RECT  2.16 49.815 12.96 50.085 ;
     RECT  2.16 50.355 12.96 50.625 ;
     RECT  2.16 50.895 12.96 51.165 ;
     RECT  2.16 51.435 12.96 51.705 ;
     RECT  2.16 51.975 12.96 52.245 ;
     RECT  2.16 52.515 12.96 52.785 ;
     RECT  2.16 53.055 12.96 53.325 ;
     RECT  2.16 53.595 12.96 53.865 ;
     RECT  2.16 54.135 12.96 54.405 ;
     RECT  2.16 54.675 12.96 54.945 ;
     RECT  2.16 55.215 12.96 55.485 ;
     RECT  2.16 55.755 12.96 56.025 ;
     RECT  2.16 56.295 12.96 56.565 ;
     RECT  2.16 56.835 12.96 57.105 ;
     RECT  2.16 57.375 12.96 57.645 ;
     RECT  2.16 57.915 12.96 58.185 ;
     RECT  2.16 58.455 12.96 58.725 ;
     RECT  2.16 58.995 12.96 59.265 ;
     RECT  2.16 59.535 12.96 59.805 ;
     RECT  2.16 60.075 12.96 60.345 ;
     RECT  2.16 60.615 12.96 60.885 ;
     RECT  2.16 61.155 12.96 61.425 ;
     RECT  2.16 61.695 12.96 61.965 ;
     RECT  2.16 62.235 12.96 62.505 ;
    LAYER M1 ;
     RECT  2.16 2.151 12.96 62.649 ;
    LAYER M2 ;
     RECT  0.067 46.746 0.167 46.764 ;
     RECT  0.067 49.626 0.167 49.644 ;
     RECT  0.031 58.428 0.167 58.446 ;
     RECT  0.139 19.656 0.175 19.674 ;
     RECT  0.139 30.816 0.239 30.834 ;
     RECT  0.139 32.472 0.239 32.724 ;
     RECT  0.175 19.35 0.859 19.674 ;
     RECT  0.139 17.082 1.975 17.64 ;
     RECT  0.139 7.362 2.16 7.38 ;
     RECT  0.823 9.09 2.16 9.108 ;
     RECT  0.103 10.134 2.16 10.152 ;
     RECT  1.399 11.25 2.16 11.268 ;
     RECT  1.975 16.416 2.16 17.64 ;
     RECT  0.859 18.702 2.16 19.674 ;
     RECT  0.239 32.472 2.16 32.49 ;
     RECT  0.211 37.602 2.16 37.62 ;
     RECT  0.211 41.418 2.16 41.436 ;
     RECT  2.16 2.151 12.96 62.649 ;
     RECT  12.96 6.696 13.559 59.994 ;
     RECT  13.559 6.696 13.667 19.764 ;
     RECT  13.559 20.7 13.667 59.994 ;
     RECT  13.667 32.706 13.955 58.644 ;
     RECT  13.667 59.436 14.207 59.994 ;
     RECT  13.667 6.696 14.243 6.714 ;
     RECT  13.667 7.596 14.243 14.094 ;
     RECT  13.667 14.886 14.243 18.216 ;
     RECT  13.667 19.116 14.243 19.134 ;
     RECT  13.667 20.826 14.243 22.194 ;
     RECT  13.667 23.256 14.243 31.914 ;
     RECT  13.955 32.706 14.243 50.724 ;
     RECT  13.955 51.606 14.243 58.644 ;
     RECT  14.207 59.436 14.243 59.454 ;
     RECT  14.243 11.286 14.279 11.304 ;
     RECT  14.243 17.496 14.279 18.054 ;
     RECT  14.243 20.934 14.279 21.186 ;
     RECT  14.243 22.176 14.279 22.194 ;
     RECT  14.243 48.366 14.279 48.384 ;
     RECT  14.243 50.706 14.279 50.724 ;
     RECT  12.96 4.896 14.315 5.634 ;
     RECT  14.315 5.076 14.963 5.634 ;
     RECT  14.243 8.856 14.963 8.874 ;
     RECT  14.243 10.206 14.963 10.224 ;
     RECT  14.243 12.456 14.963 12.474 ;
     RECT  14.243 15.966 14.963 15.984 ;
     RECT  14.279 17.496 14.963 17.514 ;
     RECT  14.243 26.766 14.963 26.784 ;
     RECT  14.243 31.896 14.963 31.914 ;
     RECT  14.243 47.286 14.963 47.304 ;
    LAYER M3 ;
     RECT  2.415 2.143 2.505 2.413 ;
     RECT  5.115 2.143 5.205 2.413 ;
     RECT  7.815 2.143 7.905 2.413 ;
     RECT  10.515 2.143 10.605 2.413 ;
     RECT  14.292 4.891 14.31 5.071 ;
     RECT  12.384 5.035 12.654 5.305 ;
     RECT  14.292 5.071 14.958 5.341 ;
     RECT  2.415 2.413 2.697 5.419 ;
     RECT  12.024 5.305 12.654 5.431 ;
     RECT  11.736 5.431 12.654 5.503 ;
     RECT  11.736 5.503 13.122 5.575 ;
     RECT  2.304 5.419 2.697 5.611 ;
     RECT  10.515 2.413 10.797 5.611 ;
     RECT  11.664 5.575 13.122 5.611 ;
     RECT  10.515 5.611 13.122 5.693 ;
     RECT  5.115 2.413 5.397 5.737 ;
     RECT  9.648 0.523 9.666 5.737 ;
     RECT  10.515 5.693 12.834 5.737 ;
     RECT  9.576 5.737 12.834 5.765 ;
     RECT  5.115 5.737 5.67 5.773 ;
     RECT  6.444 5.737 6.462 5.773 ;
     RECT  7.815 2.413 8.097 5.773 ;
     RECT  7.815 5.773 8.442 5.809 ;
     RECT  7.815 5.809 8.838 5.881 ;
     RECT  9.576 5.765 10.962 5.881 ;
     RECT  2.304 5.611 3.006 5.899 ;
     RECT  7.815 5.881 10.962 5.999 ;
     RECT  2.268 5.899 3.006 6.007 ;
     RECT  5.115 5.773 6.894 6.007 ;
     RECT  9.576 5.999 10.962 6.035 ;
     RECT  2.268 6.007 3.438 6.091 ;
     RECT  4.644 6.007 6.894 6.115 ;
     RECT  7.815 5.999 8.838 6.115 ;
     RECT  2.268 6.091 3.654 6.143 ;
     RECT  2.304 6.143 3.654 6.151 ;
     RECT  4.644 6.115 8.838 6.151 ;
     RECT  14.256 5.341 14.958 6.509 ;
     RECT  9.648 6.035 10.962 6.691 ;
     RECT  11.736 5.765 12.834 6.691 ;
     RECT  14.22 6.691 14.238 6.797 ;
     RECT  2.304 6.151 8.838 6.845 ;
     RECT  2.304 6.845 8.262 6.917 ;
     RECT  9.648 6.691 12.834 7.085 ;
     RECT  9.648 7.085 12.474 7.195 ;
     RECT  13.644 7.291 13.662 7.349 ;
     RECT  2.304 6.917 8.226 7.735 ;
     RECT  9.504 7.195 12.474 7.735 ;
     RECT  0.144 6.091 0.162 7.757 ;
     RECT  2.304 7.735 12.474 7.889 ;
     RECT  14.22 7.579 14.238 8.683 ;
     RECT  2.304 7.889 12.33 8.815 ;
     RECT  13.644 8.683 14.238 8.851 ;
     RECT  2.304 8.815 12.51 8.969 ;
     RECT  13.644 8.851 14.958 8.969 ;
     RECT  2.304 8.969 11.754 9.005 ;
     RECT  14.22 8.969 14.958 9.245 ;
     RECT  12.492 8.969 12.51 9.517 ;
     RECT  12.492 9.517 12.69 9.689 ;
     RECT  4.824 9.005 11.754 9.751 ;
     RECT  14.22 9.245 14.238 9.821 ;
     RECT  4.824 9.751 12.438 9.851 ;
     RECT  2.304 9.005 3.87 10.021 ;
     RECT  2.304 10.021 3.906 10.085 ;
     RECT  4.824 9.851 12.402 10.121 ;
     RECT  0.828 9.085 0.846 10.129 ;
     RECT  2.34 10.085 3.906 10.165 ;
     RECT  4.824 10.121 11.97 10.165 ;
     RECT  14.94 10.201 14.958 10.349 ;
     RECT  2.34 10.165 11.97 10.493 ;
     RECT  2.34 10.493 7.074 10.637 ;
     RECT  13.644 10.027 13.662 10.831 ;
     RECT  7.815 10.493 11.97 11.011 ;
     RECT  0.108 10.129 0.846 11.245 ;
     RECT  7.815 11.011 12.006 11.245 ;
     RECT  13.644 10.831 14.238 11.281 ;
     RECT  2.415 10.637 7.074 11.419 ;
     RECT  7.815 11.245 12.582 11.419 ;
     RECT  13.644 11.281 14.274 11.453 ;
     RECT  2.415 11.419 12.582 11.515 ;
     RECT  2.415 11.515 12.654 11.669 ;
     RECT  7.815 11.669 12.51 11.741 ;
     RECT  13.644 11.453 14.238 11.741 ;
     RECT  12.492 11.741 12.51 12.011 ;
     RECT  2.415 11.669 7.074 12.187 ;
     RECT  14.22 11.741 14.238 12.451 ;
     RECT  14.22 12.451 14.958 12.557 ;
     RECT  2.304 12.187 7.074 12.631 ;
     RECT  7.815 11.741 11.682 12.631 ;
     RECT  2.304 12.631 11.682 12.901 ;
     RECT  2.304 12.901 11.79 13.171 ;
     RECT  2.304 13.171 12.042 13.675 ;
     RECT  2.304 13.675 12.474 13.865 ;
     RECT  4.392 13.865 12.474 13.901 ;
     RECT  2.304 13.865 3.51 14.011 ;
     RECT  2.268 14.011 3.51 14.135 ;
     RECT  4.392 13.901 6.21 14.135 ;
     RECT  14.22 12.557 14.238 14.155 ;
     RECT  13.644 14.155 14.238 14.443 ;
     RECT  2.304 14.135 3.51 14.635 ;
     RECT  4.392 14.135 5.397 14.635 ;
     RECT  7.236 13.901 12.474 14.819 ;
     RECT  7.236 14.819 8.694 14.909 ;
     RECT  2.304 14.635 5.397 14.917 ;
     RECT  6.192 14.135 6.21 14.917 ;
     RECT  9.576 14.819 12.474 14.917 ;
     RECT  13.608 14.443 14.238 14.953 ;
     RECT  13.572 14.953 14.238 15.005 ;
     RECT  13.608 15.005 14.238 15.017 ;
     RECT  9.576 14.917 12.582 15.089 ;
     RECT  9.576 15.089 12.546 15.179 ;
     RECT  2.304 14.917 6.21 15.259 ;
     RECT  2.268 15.259 6.21 15.331 ;
     RECT  2.268 15.331 6.462 15.389 ;
     RECT  2.415 15.389 6.462 15.457 ;
     RECT  7.236 14.909 8.622 15.457 ;
     RECT  14.22 15.017 14.238 15.787 ;
     RECT  2.415 15.457 8.622 15.829 ;
     RECT  14.22 15.787 14.958 15.989 ;
     RECT  2.415 15.829 8.838 16.025 ;
     RECT  4.32 16.025 8.838 16.069 ;
     RECT  9.576 15.179 11.97 16.069 ;
     RECT  4.32 16.069 11.97 16.141 ;
     RECT  4.32 16.141 12.474 16.331 ;
     RECT  0.108 11.245 1.422 16.411 ;
     RECT  2.415 16.025 3.402 16.411 ;
     RECT  14.22 15.989 14.238 16.603 ;
     RECT  4.32 16.331 9.702 16.637 ;
     RECT  10.515 16.331 12.474 16.645 ;
     RECT  10.515 16.645 12.546 16.799 ;
     RECT  13.572 16.603 14.238 16.979 ;
     RECT  5.076 16.637 9.702 17.113 ;
     RECT  10.515 16.799 11.934 17.113 ;
     RECT  14.22 16.979 14.238 17.467 ;
     RECT  14.22 17.467 14.958 17.519 ;
     RECT  5.076 17.113 11.934 17.725 ;
     RECT  4.32 16.637 4.338 17.851 ;
     RECT  5.076 17.725 12.078 17.851 ;
     RECT  14.22 17.519 14.274 18.059 ;
     RECT  4.32 17.851 12.078 18.121 ;
     RECT  4.32 18.121 12.546 18.265 ;
     RECT  14.22 18.059 14.238 18.317 ;
     RECT  0.108 16.411 3.402 18.475 ;
     RECT  4.32 18.265 12.654 18.475 ;
     RECT  13.644 18.523 13.662 19.099 ;
     RECT  13.644 19.099 14.238 19.139 ;
     RECT  0.108 18.475 12.654 19.373 ;
     RECT  0.108 19.373 8.586 19.853 ;
     RECT  13.644 19.139 13.662 19.915 ;
     RECT  0.108 19.853 3.366 20.039 ;
     RECT  13.536 19.915 13.662 20.147 ;
     RECT  4.32 19.853 8.586 20.149 ;
     RECT  9.432 19.373 12.654 20.149 ;
     RECT  4.32 20.149 12.654 20.189 ;
     RECT  0.108 20.039 3.33 20.381 ;
     RECT  13.644 20.147 13.662 20.443 ;
     RECT  9.432 20.189 12.654 20.579 ;
     RECT  13.644 20.443 14.274 21.191 ;
     RECT  4.32 20.189 8.55 21.211 ;
     RECT  9.432 20.579 12.294 21.211 ;
     RECT  13.644 21.191 14.238 21.299 ;
     RECT  4.32 21.211 12.294 21.389 ;
     RECT  0.108 20.381 2.862 21.505 ;
     RECT  4.32 21.389 12.222 21.541 ;
     RECT  0.108 21.505 2.934 21.775 ;
     RECT  0.108 21.775 3.186 21.931 ;
     RECT  3.996 21.541 12.222 21.931 ;
     RECT  14.22 21.299 14.238 22.081 ;
     RECT  13.644 22.081 14.238 22.171 ;
     RECT  0.108 21.931 12.222 22.307 ;
     RECT  10.512 22.307 12.222 22.315 ;
     RECT  13.644 22.171 14.274 22.397 ;
     RECT  0.108 22.307 9.702 22.469 ;
     RECT  10.512 22.315 12.654 22.469 ;
     RECT  10.512 22.469 12.186 22.505 ;
     RECT  10.515 22.505 12.186 23.009 ;
     RECT  13.644 22.397 13.662 23.009 ;
     RECT  10.515 23.009 11.61 23.279 ;
     RECT  0.108 22.469 9.522 23.315 ;
     RECT  10.515 23.279 10.797 23.323 ;
     RECT  0.108 23.315 8.658 23.585 ;
     RECT  12.6 23.521 12.618 23.621 ;
     RECT  10.26 23.323 10.797 23.819 ;
     RECT  11.52 23.279 11.61 24.061 ;
     RECT  3.672 23.585 8.658 24.097 ;
     RECT  9.432 23.315 9.522 24.097 ;
     RECT  3.672 24.097 9.522 24.161 ;
     RECT  11.52 24.061 11.754 24.161 ;
     RECT  10.515 23.819 10.797 24.205 ;
     RECT  11.52 24.161 11.538 24.205 ;
     RECT  14.22 23.179 14.238 24.283 ;
     RECT  3.672 24.161 9.45 24.359 ;
     RECT  13.644 24.283 14.238 24.359 ;
     RECT  0.108 23.585 2.697 24.427 ;
     RECT  3.672 24.359 6.57 24.427 ;
     RECT  12.276 24.331 12.294 24.431 ;
     RECT  0.108 24.427 6.57 24.665 ;
     RECT  3.42 24.665 6.57 24.701 ;
     RECT  10.515 24.205 11.538 25.411 ;
     RECT  3.672 24.701 6.57 25.447 ;
     RECT  7.308 24.359 9.45 25.447 ;
     RECT  3.672 25.447 9.45 25.475 ;
     RECT  0.108 24.665 2.697 25.531 ;
     RECT  3.672 25.475 8.658 25.531 ;
     RECT  10.515 25.411 11.754 25.861 ;
     RECT  12.528 25.825 12.546 25.861 ;
     RECT  10.515 25.861 12.546 26.095 ;
     RECT  0.108 25.531 8.658 26.257 ;
     RECT  9.432 25.475 9.45 26.257 ;
     RECT  10.515 26.095 12.618 26.401 ;
     RECT  14.22 24.359 14.238 26.528 ;
     RECT  0.108 26.257 9.45 26.627 ;
     RECT  10.332 26.401 12.618 26.789 ;
     RECT  14.94 26.761 14.958 26.813 ;
     RECT  10.515 26.789 12.618 27.019 ;
     RECT  10.515 27.019 13.086 27.131 ;
     RECT  7.308 26.627 9.45 27.365 ;
     RECT  10.515 27.131 12.402 27.599 ;
     RECT  7.416 27.365 9.45 27.751 ;
     RECT  7.416 27.751 9.774 28.139 ;
     RECT  7.416 28.139 9.45 28.255 ;
     RECT  0.108 26.627 6.462 28.381 ;
     RECT  7.308 28.255 9.45 28.381 ;
     RECT  0.108 28.381 9.45 28.409 ;
     RECT  0.108 28.409 8.262 28.481 ;
     RECT  10.515 27.599 11.79 28.679 ;
     RECT  7.272 28.481 8.154 29.335 ;
     RECT  9.036 28.409 9.45 29.335 ;
     RECT  7.272 29.335 9.45 29.489 ;
     RECT  0.108 28.481 6.462 29.497 ;
     RECT  7.272 29.489 8.154 29.497 ;
     RECT  0.108 29.497 8.154 29.525 ;
     RECT  6.912 29.525 8.154 29.597 ;
     RECT  0.108 29.525 6.138 30.331 ;
     RECT  9.036 29.489 9.45 30.415 ;
     RECT  0.108 30.331 6.462 30.577 ;
     RECT  7.272 29.597 8.154 30.577 ;
     RECT  8.928 30.415 9.45 30.605 ;
     RECT  9.036 30.605 9.45 30.721 ;
     RECT  0.108 30.577 8.154 30.839 ;
     RECT  10.515 28.679 11.682 31.225 ;
     RECT  7.2 30.839 8.154 31.387 ;
     RECT  9.036 30.721 9.702 31.387 ;
     RECT  7.2 31.387 9.702 31.531 ;
     RECT  10.515 31.225 11.754 31.531 ;
     RECT  7.2 31.531 11.754 31.685 ;
     RECT  0.108 30.839 6.462 31.693 ;
     RECT  7.2 31.685 8.262 31.693 ;
     RECT  14.22 27.301 14.238 31.721 ;
     RECT  12.492 31.891 12.51 31.991 ;
     RECT  14.94 31.891 14.958 31.997 ;
     RECT  9.036 31.685 11.754 32.071 ;
     RECT  0.108 31.693 8.262 32.369 ;
     RECT  9.036 32.071 12.366 32.495 ;
     RECT  10.224 32.495 12.078 32.531 ;
     RECT  13.644 32.251 13.662 32.539 ;
     RECT  7.2 32.369 8.262 32.575 ;
     RECT  9.036 32.495 9.45 32.575 ;
     RECT  7.2 32.575 9.45 32.603 ;
     RECT  7.272 32.603 9.45 32.729 ;
     RECT  10.224 32.531 11.754 32.729 ;
     RECT  13.644 32.539 14.238 32.999 ;
     RECT  0.108 32.369 6.462 33.035 ;
     RECT  3.672 33.035 6.462 33.269 ;
     RECT  10.515 32.729 11.754 33.341 ;
     RECT  7.272 32.729 8.262 33.385 ;
     RECT  6.228 33.269 6.462 33.539 ;
     RECT  6.336 33.539 6.462 33.611 ;
     RECT  7.2 33.385 8.262 33.655 ;
     RECT  9.036 32.729 9.45 33.655 ;
     RECT  7.2 33.655 9.45 33.683 ;
     RECT  7.416 33.683 9.45 33.809 ;
     RECT  0.108 33.035 2.697 33.817 ;
     RECT  3.672 33.269 5.397 33.817 ;
     RECT  14.22 32.999 14.238 33.883 ;
     RECT  13.644 33.883 14.238 33.989 ;
     RECT  12.528 33.961 12.546 34.079 ;
     RECT  0.108 33.817 5.397 34.087 ;
     RECT  12.6 34.195 12.618 34.349 ;
     RECT  0.108 34.087 5.598 34.363 ;
     RECT  6.336 33.611 6.354 34.363 ;
     RECT  0.108 34.363 6.354 34.421 ;
     RECT  7.416 33.809 8.262 34.465 ;
     RECT  10.515 33.341 11.682 34.501 ;
     RECT  6.12 34.421 6.354 34.591 ;
     RECT  6.12 34.591 6.426 34.747 ;
     RECT  7.272 34.465 8.262 34.771 ;
     RECT  9.036 33.809 9.45 34.771 ;
     RECT  6.12 34.747 6.498 34.799 ;
     RECT  7.272 34.771 9.45 35.041 ;
     RECT  10.26 34.501 11.682 35.041 ;
     RECT  0.108 34.421 5.397 35.275 ;
     RECT  6.12 34.799 6.462 35.275 ;
     RECT  0.108 35.275 6.462 35.581 ;
     RECT  7.272 35.041 11.682 35.581 ;
     RECT  0.108 35.581 11.682 35.735 ;
     RECT  7.416 35.735 11.682 35.815 ;
     RECT  7.416 35.815 11.754 36.005 ;
     RECT  10.08 36.005 11.754 36.121 ;
     RECT  12.528 36.085 12.546 36.121 ;
     RECT  10.08 36.121 12.546 36.239 ;
     RECT  10.08 36.239 11.97 36.275 ;
     RECT  0.108 35.735 6.642 36.589 ;
     RECT  7.416 36.005 9.198 36.589 ;
     RECT  0.108 36.589 9.198 36.859 ;
     RECT  0.108 36.859 9.234 36.931 ;
     RECT  10.515 36.275 11.97 37.085 ;
     RECT  14.22 33.989 14.238 37.195 ;
     RECT  0.108 36.931 9.486 37.201 ;
     RECT  12.456 37.201 12.618 37.355 ;
     RECT  0.108 37.201 9.774 37.427 ;
     RECT  6.228 37.427 9.774 37.471 ;
     RECT  10.515 37.085 11.178 37.471 ;
     RECT  14.184 37.195 14.238 37.723 ;
     RECT  6.228 37.471 11.178 37.831 ;
     RECT  12.456 37.355 12.474 37.895 ;
     RECT  6.228 37.831 11.646 37.939 ;
     RECT  13.644 37.723 14.238 37.939 ;
     RECT  13.608 37.939 14.238 38.045 ;
     RECT  13.644 38.045 14.238 38.129 ;
     RECT  6.228 37.939 12.366 38.165 ;
     RECT  0.108 37.427 5.397 38.173 ;
     RECT  6.228 38.165 11.97 38.173 ;
     RECT  0.108 38.173 11.97 38.741 ;
     RECT  0.108 38.741 11.754 38.765 ;
     RECT  10.044 38.765 11.754 39.281 ;
     RECT  10.044 39.281 11.682 39.479 ;
     RECT  0.108 38.765 9.198 39.865 ;
     RECT  10.044 39.479 11.538 39.865 ;
     RECT  0.108 39.865 11.538 40.055 ;
     RECT  0.108 40.055 9.198 40.163 ;
     RECT  3.456 40.163 9.198 40.289 ;
     RECT  10.332 40.055 11.538 40.675 ;
     RECT  3.456 40.289 9.054 40.901 ;
     RECT  10.332 40.675 11.682 40.909 ;
     RECT  0.108 40.163 2.697 40.981 ;
     RECT  3.456 40.901 8.298 40.981 ;
     RECT  10.296 40.909 11.682 40.981 ;
     RECT  0.108 40.981 8.298 41.099 ;
     RECT  10.26 40.981 11.682 41.099 ;
     RECT  10.296 41.099 11.682 41.611 ;
     RECT  10.296 41.611 11.754 41.711 ;
     RECT  10.296 41.711 11.682 41.909 ;
     RECT  9.036 40.901 9.054 41.917 ;
     RECT  8.892 41.917 9.054 42.061 ;
     RECT  10.296 41.909 11.61 42.061 ;
     RECT  0.108 41.099 8.097 42.089 ;
     RECT  8.892 42.061 11.61 42.215 ;
     RECT  14.22 38.129 14.238 42.379 ;
     RECT  12.6 42.331 12.618 42.485 ;
     RECT  0.108 42.089 6.642 42.835 ;
     RECT  7.416 42.089 8.097 42.835 ;
     RECT  9.036 42.215 11.61 42.835 ;
     RECT  9.036 42.835 11.682 42.989 ;
     RECT  9.036 42.989 9.054 43.105 ;
     RECT  9.828 42.989 11.682 43.231 ;
     RECT  8.892 43.105 9.054 43.403 ;
     RECT  9.828 43.231 12.222 43.771 ;
     RECT  0.108 42.835 8.097 43.799 ;
     RECT  9.828 43.771 12.294 43.799 ;
     RECT  13.644 42.379 14.238 43.808 ;
     RECT  10.515 43.799 12.294 43.871 ;
     RECT  0.108 43.799 6.462 43.901 ;
     RECT  7.308 43.799 8.097 44.069 ;
     RECT  0.108 43.901 6.354 44.141 ;
     RECT  7.38 44.069 8.097 44.141 ;
     RECT  10.515 43.871 11.754 44.141 ;
     RECT  7.416 44.141 8.097 44.185 ;
     RECT  9.036 43.403 9.054 44.185 ;
     RECT  14.22 43.808 14.238 44.875 ;
     RECT  13.644 44.875 14.238 44.915 ;
     RECT  7.416 44.185 9.054 44.995 ;
     RECT  10.515 44.141 11.646 44.995 ;
     RECT  0.108 44.141 6.174 45.115 ;
     RECT  7.308 44.995 9.054 45.115 ;
     RECT  10.515 44.995 12.294 45.149 ;
     RECT  10.515 45.149 12.15 45.761 ;
     RECT  14.22 44.915 14.238 45.931 ;
     RECT  0.108 45.115 9.054 45.995 ;
     RECT  0.108 45.995 6.642 46.109 ;
     RECT  10.515 45.761 12.078 46.409 ;
     RECT  13.644 45.931 14.238 46.541 ;
     RECT  0.108 46.109 6.498 46.741 ;
     RECT  7.416 45.995 9.054 46.741 ;
     RECT  10.515 46.409 11.862 47.039 ;
     RECT  0.072 46.741 6.498 47.191 ;
     RECT  7.308 46.741 9.054 47.191 ;
     RECT  10.515 47.039 11.754 47.281 ;
     RECT  14.22 46.541 14.238 47.281 ;
     RECT  0.072 47.191 9.054 47.309 ;
     RECT  8.928 47.309 9.054 47.345 ;
     RECT  14.22 47.281 14.958 47.357 ;
     RECT  9.972 47.281 11.754 47.615 ;
     RECT  10.515 47.615 11.754 48.001 ;
     RECT  10.515 48.001 12.042 48.191 ;
     RECT  7.308 47.309 8.097 48.235 ;
     RECT  9.036 47.345 9.054 48.235 ;
     RECT  14.22 47.357 14.238 48.361 ;
     RECT  8.928 48.235 9.054 48.425 ;
     RECT  9.036 48.425 9.054 48.541 ;
     RECT  0.072 47.309 6.498 48.667 ;
     RECT  7.308 48.235 8.154 48.667 ;
     RECT  14.22 48.361 14.274 48.749 ;
     RECT  9.036 48.541 9.594 48.775 ;
     RECT  0.072 48.667 8.154 48.839 ;
     RECT  10.515 48.191 11.97 49.081 ;
     RECT  10.515 49.081 12.222 49.315 ;
     RECT  7.308 48.839 8.154 49.351 ;
     RECT  9.036 48.775 9.702 49.351 ;
     RECT  10.515 49.315 12.438 49.469 ;
     RECT  7.308 49.351 9.702 49.505 ;
     RECT  9.036 49.505 9.702 49.513 ;
     RECT  10.515 49.469 12.402 49.513 ;
     RECT  0.072 48.839 6.498 49.649 ;
     RECT  0.108 49.649 6.498 49.747 ;
     RECT  7.308 49.505 8.298 49.747 ;
     RECT  0.108 49.747 8.298 50.279 ;
     RECT  9.036 49.513 12.402 50.279 ;
     RECT  14.22 48.749 14.238 50.347 ;
     RECT  9.036 50.279 9.054 50.395 ;
     RECT  8.928 50.395 9.054 50.585 ;
     RECT  13.788 50.347 14.238 50.635 ;
     RECT  13.644 50.635 14.238 50.701 ;
     RECT  13.644 50.701 14.274 50.891 ;
     RECT  9.9 50.279 12.402 50.935 ;
     RECT  13.932 50.891 14.274 50.963 ;
     RECT  9.9 50.935 12.618 51.089 ;
     RECT  14.22 50.963 14.274 51.197 ;
     RECT  9.9 51.089 12.402 51.359 ;
     RECT  12.168 51.359 12.186 51.395 ;
     RECT  9.036 50.585 9.054 51.475 ;
     RECT  8.928 51.475 9.054 51.511 ;
     RECT  0.108 50.279 8.19 51.601 ;
     RECT  8.928 51.511 9.45 51.601 ;
     RECT  0.108 51.601 9.45 51.629 ;
     RECT  0.108 51.629 8.226 51.809 ;
     RECT  10.515 51.359 11.322 52.141 ;
     RECT  10.515 52.141 11.754 52.241 ;
     RECT  0.108 51.809 8.19 52.439 ;
     RECT  7.272 52.439 8.19 52.475 ;
     RECT  7.416 52.475 8.19 52.591 ;
     RECT  9.036 51.629 9.45 52.591 ;
     RECT  7.416 52.591 9.45 52.745 ;
     RECT  9.036 52.745 9.45 52.951 ;
     RECT  10.515 52.241 11.574 52.951 ;
     RECT  0.108 52.439 6.462 53.015 ;
     RECT  7.416 52.745 8.262 53.257 ;
     RECT  7.308 53.257 8.262 53.365 ;
     RECT  9.036 52.951 11.574 53.365 ;
     RECT  9.036 53.365 11.682 53.491 ;
     RECT  7.2 53.365 8.262 53.519 ;
     RECT  9.036 53.491 11.754 53.635 ;
     RECT  7.2 53.519 8.19 53.663 ;
     RECT  8.928 53.635 11.754 53.789 ;
     RECT  0.108 53.015 2.697 53.797 ;
     RECT  3.888 53.015 6.462 53.797 ;
     RECT  10.152 53.789 11.754 54.175 ;
     RECT  10.152 54.175 11.79 54.329 ;
     RECT  7.416 53.663 8.19 54.337 ;
     RECT  8.928 53.789 9.378 54.337 ;
     RECT  7.416 54.337 9.378 54.445 ;
     RECT  10.152 54.329 11.61 54.599 ;
     RECT  7.272 54.445 9.378 54.635 ;
     RECT  7.272 54.635 8.19 54.869 ;
     RECT  10.515 54.599 11.61 55.139 ;
     RECT  0.108 53.797 6.462 55.147 ;
     RECT  7.272 54.869 8.154 55.147 ;
     RECT  14.22 51.197 14.238 55.183 ;
     RECT  12.528 55.111 12.546 55.255 ;
     RECT  0.108 55.147 8.154 55.319 ;
     RECT  13.68 55.183 14.238 55.325 ;
     RECT  12.348 55.255 12.654 55.409 ;
     RECT  9.036 54.635 9.378 55.525 ;
     RECT  12.6 55.409 12.618 55.751 ;
     RECT  8.892 55.525 9.378 55.823 ;
     RECT  10.515 55.139 11.538 55.831 ;
     RECT  10.26 55.831 11.538 55.921 ;
     RECT  0.108 55.319 6.858 56.335 ;
     RECT  0.108 56.335 6.894 56.371 ;
     RECT  7.632 55.319 8.154 56.371 ;
     RECT  0.108 56.371 8.154 56.561 ;
     RECT  9 55.823 9.378 56.605 ;
     RECT  14.22 55.325 14.238 56.632 ;
     RECT  8.892 56.605 9.378 56.641 ;
     RECT  10.26 55.921 11.754 56.641 ;
     RECT  7.164 56.561 8.154 56.669 ;
     RECT  14.184 56.632 14.238 56.669 ;
     RECT  7.452 56.669 8.154 56.759 ;
     RECT  8.892 56.641 11.754 56.795 ;
     RECT  8.892 56.795 11.466 56.831 ;
     RECT  8.892 56.831 9.378 56.903 ;
     RECT  7.632 56.759 8.154 56.939 ;
     RECT  0.108 56.561 6.21 57.029 ;
     RECT  4.32 57.029 6.21 57.299 ;
     RECT  7.632 56.939 8.097 57.299 ;
     RECT  0.108 57.029 2.754 57.335 ;
     RECT  4.32 57.299 5.67 57.335 ;
     RECT  9 56.903 9.378 57.569 ;
     RECT  0.108 57.335 2.697 57.581 ;
     RECT  1.98 57.581 2.697 57.821 ;
     RECT  10.26 56.831 11.466 57.839 ;
     RECT  10.515 57.839 11.466 57.847 ;
     RECT  10.515 57.847 11.574 57.919 ;
     RECT  10.515 57.919 11.646 58.081 ;
     RECT  6.84 57.919 6.858 58.109 ;
     RECT  0.108 57.581 0.882 58.219 ;
     RECT  10.515 58.081 12.078 58.261 ;
     RECT  14.22 56.669 14.238 58.267 ;
     RECT  10.515 58.261 12.618 58.415 ;
     RECT  4.32 57.335 5.397 58.541 ;
     RECT  10.515 58.415 12.294 58.649 ;
     RECT  11.952 58.649 12.294 58.721 ;
     RECT  0.036 58.219 0.882 58.877 ;
     RECT  13.644 58.267 14.238 58.919 ;
     RECT  0.036 58.877 0.234 59.165 ;
     RECT  9.36 57.569 9.378 59.189 ;
     RECT  12.276 58.721 12.294 59.233 ;
     RECT  0.036 59.165 0.054 59.405 ;
     RECT  10.515 58.649 10.854 59.459 ;
     RECT  14.148 58.919 14.238 59.459 ;
     RECT  12.276 59.233 12.582 59.611 ;
     RECT  4.68 58.541 5.397 59.729 ;
     RECT  14.148 59.459 14.202 59.729 ;
     RECT  11.988 59.611 12.618 59.801 ;
     RECT  14.184 59.729 14.202 59.999 ;
     RECT  12.6 59.801 12.618 60.035 ;
     RECT  2.415 57.821 2.697 62.387 ;
     RECT  5.115 59.729 5.397 62.387 ;
     RECT  7.815 57.299 8.097 62.387 ;
     RECT  10.515 59.459 10.797 62.387 ;
     RECT  2.415 62.387 2.505 62.657 ;
     RECT  5.115 62.387 5.205 62.657 ;
     RECT  7.815 62.387 7.905 62.657 ;
     RECT  10.515 62.387 10.605 62.657 ;
    LAYER M4 ;
     RECT  0.085 1.392 0.108 1.416 ;
     RECT  0.085 31.728 0.108 31.752 ;
     RECT  0.108 5.424 0.245 59.16 ;
     RECT  0.245 5.424 0.893 58.872 ;
     RECT  0.893 5.424 2.408 58.536 ;
     RECT  2.408 2.148 2.512 62.652 ;
     RECT  2.512 2.418 2.704 62.382 ;
     RECT  2.704 56.256 2.729 57.048 ;
     RECT  2.704 25.536 2.765 27.384 ;
     RECT  2.729 56.4 2.765 57.048 ;
     RECT  2.704 43.392 2.801 43.416 ;
     RECT  2.704 44.976 2.801 49.56 ;
     RECT  2.704 10.128 2.837 11.976 ;
     RECT  2.704 28.704 2.837 29.112 ;
     RECT  2.704 33.84 2.873 39.912 ;
     RECT  2.801 48.72 2.873 49.56 ;
     RECT  2.801 44.976 2.909 47.352 ;
     RECT  2.873 37.008 3.089 39.912 ;
     RECT  2.704 30.24 3.197 31.752 ;
     RECT  3.089 37.008 3.197 38.184 ;
     RECT  2.909 45.504 3.197 47.352 ;
     RECT  2.837 10.128 3.233 11.688 ;
     RECT  2.704 14.64 3.233 16.296 ;
     RECT  2.704 23.28 3.251 23.4 ;
     RECT  3.089 39.264 3.299 39.912 ;
     RECT  2.765 25.536 3.305 25.56 ;
     RECT  3.197 37.008 3.34 38.04 ;
     RECT  2.873 48.72 3.341 48.744 ;
     RECT  2.873 33.84 3.347 36.024 ;
     RECT  2.704 51.648 3.347 51.672 ;
     RECT  2.704 52.752 3.347 52.776 ;
     RECT  2.704 53.808 3.347 54.744 ;
     RECT  3.34 37.008 3.377 37.656 ;
     RECT  3.347 54.72 3.377 54.744 ;
     RECT  2.704 6.096 3.665 7.224 ;
     RECT  3.197 31.344 3.685 31.752 ;
     RECT  2.704 32.784 3.685 32.808 ;
     RECT  3.685 31.344 3.731 32.808 ;
     RECT  3.665 6.816 3.737 7.224 ;
     RECT  2.704 18.48 3.773 19.848 ;
     RECT  2.765 26.592 3.829 27.384 ;
     RECT  3.829 26.592 3.841 27.672 ;
     RECT  3.233 14.64 3.845 15.816 ;
     RECT  2.704 21.936 3.877 21.96 ;
     RECT  3.347 34.176 3.889 36.024 ;
     RECT  3.197 46.176 3.949 47.352 ;
     RECT  3.845 14.64 3.953 15.768 ;
     RECT  3.877 21.936 3.971 22.2 ;
     RECT  3.877 25.488 3.971 25.512 ;
     RECT  3.841 26.592 3.971 27.912 ;
     RECT  3.971 21.936 3.973 21.96 ;
     RECT  3.973 20.976 4.019 21.96 ;
     RECT  3.251 23.376 4.025 23.4 ;
     RECT  3.773 19.008 4.061 19.848 ;
     RECT  3.233 10.896 4.201 11.688 ;
     RECT  3.197 30.24 4.273 30.264 ;
     RECT  3.731 31.344 4.273 32.52 ;
     RECT  4.201 10.8 4.453 11.688 ;
     RECT  4.453 10.8 4.489 11.928 ;
     RECT  4.019 20.976 4.489 21 ;
     RECT  4.489 10.8 4.525 12.792 ;
     RECT  3.971 26.736 4.549 27.912 ;
     RECT  2.837 29.088 4.549 29.112 ;
     RECT  3.377 37.104 4.769 37.656 ;
     RECT  2.704 41.136 4.769 41.16 ;
     RECT  4.769 37.008 4.789 37.656 ;
     RECT  3.299 39.888 4.789 39.912 ;
     RECT  4.769 41.136 4.789 41.64 ;
     RECT  2.765 56.4 4.789 56.424 ;
     RECT  2.704 24.432 4.813 24.456 ;
     RECT  3.889 34.8 4.813 36.024 ;
     RECT  4.789 37.008 4.813 38.424 ;
     RECT  3.949 46.176 4.837 47.4 ;
     RECT  4.837 46.128 4.923 47.4 ;
     RECT  4.061 19.008 5.029 19.032 ;
     RECT  4.813 23.904 5.101 24.744 ;
     RECT  4.813 6.816 5.108 6.84 ;
     RECT  4.489 7.92 5.108 7.992 ;
     RECT  4.525 10.8 5.108 13.08 ;
     RECT  3.953 15.264 5.108 15.768 ;
     RECT  5.029 18.144 5.108 19.032 ;
     RECT  4.489 20.592 5.108 21 ;
     RECT  4.957 22.032 5.108 22.056 ;
     RECT  5.101 23.136 5.108 24.744 ;
     RECT  4.549 26.736 5.108 29.112 ;
     RECT  4.273 30.24 5.108 32.52 ;
     RECT  4.813 34.8 5.108 38.424 ;
     RECT  4.789 39.888 5.108 41.64 ;
     RECT  4.796 43.872 5.108 44.76 ;
     RECT  4.923 46.08 5.108 47.4 ;
     RECT  4.021 50.304 5.108 50.328 ;
     RECT  4.789 54.96 5.108 54.984 ;
     RECT  4.789 56.4 5.108 57.048 ;
     RECT  2.704 58.512 5.108 58.536 ;
     RECT  5.108 2.148 5.212 62.652 ;
     RECT  5.212 2.418 5.404 62.382 ;
     RECT  5.404 11.712 5.681 13.8 ;
     RECT  5.404 46.08 5.681 46.824 ;
     RECT  5.404 19.632 5.692 22.056 ;
     RECT  5.404 7.728 5.699 8.52 ;
     RECT  5.404 9.888 5.699 9.912 ;
     RECT  5.681 11.712 5.699 13.704 ;
     RECT  5.404 6.24 5.725 6.264 ;
     RECT  5.404 27.888 5.747 28.968 ;
     RECT  5.747 28.752 5.788 28.968 ;
     RECT  5.404 30.048 5.788 30.648 ;
     RECT  5.699 7.92 5.825 8.52 ;
     RECT  5.404 34.368 5.825 36.888 ;
     RECT  5.404 23.136 5.843 24.744 ;
     RECT  5.404 25.776 5.843 25.8 ;
     RECT  5.404 26.88 5.843 26.904 ;
     RECT  5.788 30.336 5.843 30.648 ;
     RECT  5.404 31.632 5.843 33.096 ;
     RECT  5.825 34.368 5.843 35.736 ;
     RECT  5.825 7.968 5.897 8.52 ;
     RECT  5.404 54.672 5.941 55.416 ;
     RECT  5.699 13.152 5.969 13.176 ;
     RECT  5.692 19.872 6.005 22.056 ;
     RECT  5.681 46.08 6.369 46.776 ;
     RECT  5.843 31.632 6.389 32.52 ;
     RECT  5.404 38.784 6.428 38.808 ;
     RECT  5.404 39.84 6.428 39.864 ;
     RECT  5.404 40.992 6.428 41.16 ;
     RECT  5.404 50.304 6.428 50.328 ;
     RECT  6.428 39.84 6.431 41.832 ;
     RECT  6.428 50.112 6.433 50.328 ;
     RECT  6.433 26.784 6.469 26.808 ;
     RECT  6.428 38.64 6.469 38.808 ;
     RECT  6.431 39.84 6.469 42.792 ;
     RECT  5.788 28.944 6.473 28.968 ;
     RECT  6.389 31.344 6.473 32.52 ;
     RECT  5.941 54.672 6.473 54.696 ;
     RECT  5.843 30.336 6.508 30.36 ;
     RECT  6.421 43.872 6.508 43.896 ;
     RECT  5.843 34.752 6.515 35.736 ;
     RECT  6.428 37.536 6.515 37.56 ;
     RECT  6.469 38.64 6.515 42.792 ;
     RECT  6.433 50.112 6.515 50.76 ;
     RECT  6.005 20.592 6.517 22.056 ;
     RECT  5.843 23.136 6.517 23.928 ;
     RECT  6.515 50.304 6.517 50.76 ;
     RECT  6.517 20.592 6.563 23.928 ;
     RECT  6.469 25.056 6.563 25.08 ;
     RECT  6.469 26.16 6.563 26.808 ;
     RECT  5.404 15.984 6.649 18.6 ;
     RECT  6.369 45.12 6.653 46.776 ;
     RECT  6.473 31.728 6.689 31.896 ;
     RECT  6.563 20.592 6.803 23.592 ;
     RECT  5.897 8.496 7.148 8.52 ;
     RECT  7.093 14.112 7.181 14.136 ;
     RECT  7.181 14.112 7.189 14.808 ;
     RECT  6.653 46.704 7.477 46.776 ;
     RECT  7.148 6.144 7.808 6.168 ;
     RECT  7.148 7.2 7.808 7.224 ;
     RECT  7.148 8.304 7.808 9.384 ;
     RECT  7.148 10.464 7.808 11.448 ;
     RECT  7.189 12.72 7.808 12.744 ;
     RECT  7.189 13.776 7.808 14.808 ;
     RECT  6.649 15.984 7.808 18.648 ;
     RECT  6.803 20.592 7.808 23.4 ;
     RECT  6.689 31.872 7.808 31.896 ;
     RECT  6.515 35.28 7.808 35.736 ;
     RECT  6.515 38.688 7.808 39.192 ;
     RECT  6.515 40.848 7.808 41.016 ;
     RECT  6.515 42.768 7.808 42.792 ;
     RECT  6.653 45.12 7.808 45.384 ;
     RECT  7.477 46.704 7.808 46.824 ;
     RECT  6.517 50.304 7.808 50.328 ;
     RECT  7.808 2.148 7.912 62.652 ;
     RECT  7.912 2.418 8.104 62.382 ;
     RECT  8.104 46.704 8.165 46.824 ;
     RECT  8.104 17.088 8.201 23.16 ;
     RECT  8.201 19.344 8.243 23.16 ;
     RECT  8.104 24.192 8.243 24.216 ;
     RECT  8.104 25.296 8.243 25.32 ;
     RECT  8.104 26.352 8.243 26.376 ;
     RECT  8.104 27.6 8.243 27.624 ;
     RECT  8.104 30.72 8.243 31.368 ;
     RECT  8.104 33.6 8.243 33.624 ;
     RECT  8.104 37.008 8.243 38.76 ;
     RECT  8.104 42 8.243 43.032 ;
     RECT  8.104 48.24 8.243 48.264 ;
     RECT  8.104 34.848 8.245 35.736 ;
     RECT  8.245 35.712 8.273 35.736 ;
     RECT  8.104 39.84 8.339 39.864 ;
     RECT  8.165 46.704 8.339 46.728 ;
     RECT  8.243 37.008 8.777 37.608 ;
     RECT  8.104 13.68 8.867 15.864 ;
     RECT  8.201 17.088 8.867 18.216 ;
     RECT  8.243 19.344 8.867 22.248 ;
     RECT  8.777 37.008 9.065 37.032 ;
     RECT  8.243 38.688 9.137 38.76 ;
     RECT  8.867 13.68 9.353 14.904 ;
     RECT  9.137 38.736 9.425 38.76 ;
     RECT  8.867 20.832 9.497 21.672 ;
     RECT  9.637 0.528 9.731 0.552 ;
     RECT  8.104 6.24 10.508 6.264 ;
     RECT  9.745 9.792 10.508 9.816 ;
     RECT  9.353 13.68 10.508 13.704 ;
     RECT  9.353 14.88 10.508 14.904 ;
     RECT  8.867 17.616 10.508 17.64 ;
     RECT  8.867 19.344 10.508 19.368 ;
     RECT  9.497 21.648 10.508 21.672 ;
     RECT  10.508 2.148 10.612 62.652 ;
     RECT  10.612 2.418 10.804 62.382 ;
     RECT  13.561 14.976 13.597 15 ;
     RECT  12.805 7.056 13.633 7.08 ;
     RECT  13.597 14.448 13.633 15 ;
     RECT  13.525 19.92 13.633 19.944 ;
     RECT  13.597 38.016 13.633 38.04 ;
     RECT  13.633 50.64 13.777 50.664 ;
     RECT  13.777 50.352 13.921 50.664 ;
     RECT  13.633 37.728 14.173 38.04 ;
     RECT  13.633 58.272 14.173 58.296 ;
     RECT  14.137 59.376 14.173 59.4 ;
     RECT  13.633 7.056 14.209 7.32 ;
     RECT  13.633 8.688 14.209 8.712 ;
     RECT  13.633 10.032 14.209 11.736 ;
     RECT  13.633 14.16 14.209 15 ;
     RECT  13.561 16.608 14.209 16.632 ;
     RECT  13.633 18.528 14.209 20.232 ;
     RECT  13.633 21.264 14.209 22.968 ;
     RECT  13.633 24.288 14.209 24.312 ;
     RECT  13.057 27.024 14.209 27.048 ;
     RECT  13.633 32.256 14.209 32.808 ;
     RECT  13.633 33.888 14.209 33.912 ;
     RECT  14.173 37.2 14.209 38.04 ;
     RECT  13.633 42.384 14.209 43.8 ;
     RECT  13.633 44.88 14.209 44.904 ;
     RECT  13.633 45.936 14.209 46.536 ;
     RECT  13.921 50.352 14.209 50.904 ;
     RECT  13.669 55.296 14.209 55.32 ;
     RECT  14.173 56.64 14.209 56.664 ;
     RECT  14.173 58.272 14.209 59.4 ;
     RECT  13.093 5.664 14.245 5.688 ;
     RECT  14.209 6.768 14.245 59.4 ;
     RECT  14.245 5.664 14.929 59.4 ;
     RECT  14.929 5.424 15.036 59.4 ;
    LAYER M5 ;
     RECT  0.192 1.285 0.216 1.381 ;
     RECT  0.096 1.381 0.216 1.427 ;
     RECT  2.4 2.137 2.52 2.151 ;
     RECT  5.1 2.137 5.22 2.151 ;
     RECT  7.8 2.137 7.92 2.151 ;
     RECT  10.5 2.137 10.62 2.151 ;
     RECT  7.8 2.151 8.112 6.133 ;
     RECT  5.1 2.151 5.412 6.229 ;
     RECT  5.1 6.229 5.688 9.923 ;
     RECT  5.1 9.923 5.412 11.701 ;
     RECT  7.2 6.133 8.112 14.101 ;
     RECT  7.104 14.101 8.112 14.773 ;
     RECT  7.104 14.773 8.856 18.613 ;
     RECT  5.1 11.701 5.688 21.107 ;
     RECT  5.1 21.107 5.64 21.779 ;
     RECT  2.4 2.151 2.712 21.925 ;
     RECT  3.984 20.965 4.008 21.925 ;
     RECT  2.4 21.925 4.008 21.971 ;
     RECT  6.864 18.613 8.856 22.259 ;
     RECT  6.864 22.259 8.232 22.741 ;
     RECT  6.528 22.741 8.232 23.411 ;
     RECT  2.4 21.971 3.96 23.893 ;
     RECT  5.1 21.779 5.412 23.893 ;
     RECT  6.528 23.411 6.792 23.893 ;
     RECT  2.4 23.893 6.792 26.915 ;
     RECT  2.4 26.915 5.736 27.395 ;
     RECT  7.8 23.411 8.232 27.635 ;
     RECT  3.84 27.395 5.736 27.683 ;
     RECT  4.56 27.683 5.736 28.739 ;
     RECT  4.896 28.739 5.736 28.933 ;
     RECT  6.768 26.915 6.792 28.933 ;
     RECT  4.896 28.933 6.792 28.979 ;
     RECT  7.8 27.635 8.112 30.709 ;
     RECT  7.8 30.709 8.232 31.379 ;
     RECT  0.096 1.427 0.12 31.763 ;
     RECT  2.4 27.395 2.712 32.773 ;
     RECT  3.696 31.813 3.72 32.773 ;
     RECT  2.4 32.773 3.72 32.819 ;
     RECT  7.8 31.379 8.112 33.589 ;
     RECT  2.4 32.819 3.336 34.165 ;
     RECT  2.4 34.165 3.864 34.835 ;
     RECT  7.8 33.589 8.232 34.883 ;
     RECT  5.1 28.979 6.792 35.269 ;
     RECT  7.8 34.883 8.112 35.269 ;
     RECT  5.1 35.269 8.112 35.507 ;
     RECT  3.84 34.835 3.864 36.035 ;
     RECT  2.4 34.835 2.712 36.997 ;
     RECT  5.1 35.507 5.412 36.997 ;
     RECT  6.48 35.507 8.112 38.149 ;
     RECT  4.8 36.997 5.412 38.435 ;
     RECT  2.4 36.997 3.288 39.299 ;
     RECT  6.48 38.149 8.232 39.829 ;
     RECT  5.1 38.435 5.412 40.405 ;
     RECT  4.8 40.405 5.412 41.651 ;
     RECT  6.48 39.829 8.328 42.803 ;
     RECT  5.1 41.651 5.412 43.861 ;
     RECT  6.864 42.803 8.328 43.861 ;
     RECT  6.432 43.861 8.328 45.155 ;
     RECT  6.864 45.155 8.328 46.739 ;
     RECT  4.848 43.861 5.412 46.787 ;
     RECT  6.864 46.739 8.232 48.275 ;
     RECT  6.864 48.275 8.112 50.101 ;
     RECT  6.48 50.101 8.112 50.339 ;
     RECT  6.48 50.339 6.504 50.771 ;
     RECT  2.4 39.299 2.712 51.637 ;
     RECT  5.1 46.787 5.412 54.661 ;
     RECT  2.4 51.637 3.336 54.755 ;
     RECT  5.1 54.661 5.928 54.949 ;
     RECT  4.8 54.949 5.928 55.427 ;
     RECT  4.8 55.427 5.412 57.059 ;
     RECT  2.4 54.755 2.712 62.649 ;
     RECT  5.1 57.059 5.412 62.649 ;
     RECT  7.8 50.339 8.112 62.649 ;
     RECT  10.5 2.151 10.812 62.649 ;
     RECT  2.4 62.649 2.52 62.663 ;
     RECT  5.1 62.649 5.22 62.663 ;
     RECT  7.8 62.649 7.92 62.663 ;
     RECT  10.5 62.649 10.62 62.663 ;
     RECT  5.688 6.229 7.2 9.923 ;
     RECT  5.688 11.701 7.2 14.101 ;
     RECT  5.688 14.101 7.104 18.613 ;
     RECT  5.688 18.613 6.864 21.107 ;
     RECT  2.712 20.965 3.984 21.925 ;
     RECT  4.008 20.965 5.1 21.971 ;
     RECT  5.64 21.107 6.864 21.779 ;
     RECT  5.412 21.779 6.864 22.741 ;
     RECT  3.96 21.971 5.1 23.893 ;
     RECT  5.412 22.741 6.528 23.893 ;
     RECT  6.792 23.411 7.8 35.269 ;
     RECT  5.736 26.915 6.768 28.933 ;
     RECT  2.712 27.395 3.84 27.683 ;
     RECT  2.712 31.813 3.696 32.773 ;
     RECT  3.72 31.813 5.1 32.819 ;
     RECT  3.336 32.819 5.1 34.165 ;
     RECT  3.864 34.165 5.1 36.035 ;
     RECT  2.712 34.835 3.84 36.035 ;
     RECT  5.412 35.507 6.48 42.803 ;
     RECT  2.712 36.035 5.1 36.997 ;
     RECT  3.288 36.997 4.8 38.435 ;
     RECT  5.412 42.803 6.864 43.861 ;
     RECT  5.412 43.861 6.432 45.155 ;
     RECT  5.412 45.155 6.864 50.101 ;
     RECT  5.412 50.101 6.48 50.771 ;
     RECT  6.504 50.339 7.8 50.771 ;
  END
END qwen_tx_rne_r1
END LIBRARY
